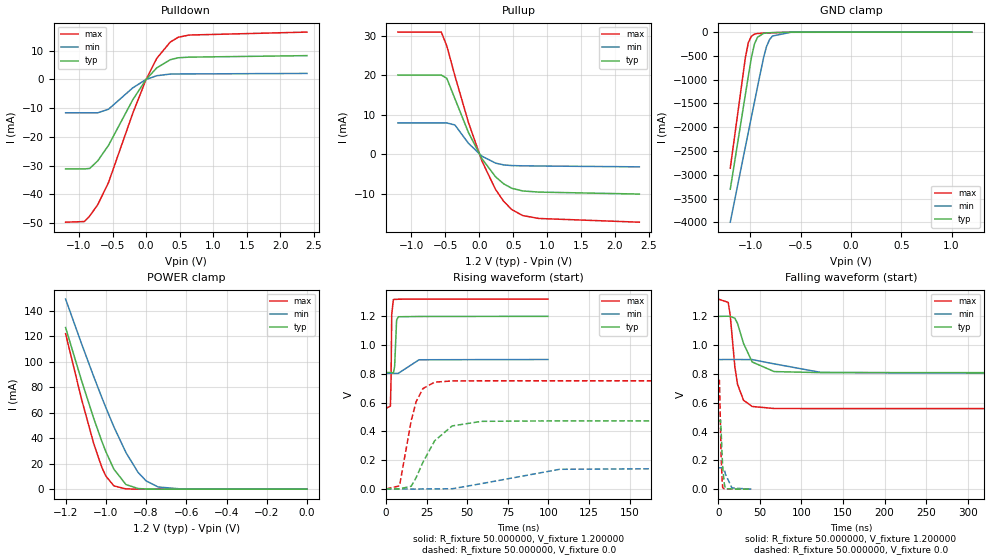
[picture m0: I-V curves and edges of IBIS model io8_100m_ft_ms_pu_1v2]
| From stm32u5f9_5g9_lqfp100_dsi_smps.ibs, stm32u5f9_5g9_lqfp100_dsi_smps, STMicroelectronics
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|   Model io8_100m_ft_ms_pu_1v2
[Model]  io8_100m_ft_ms_pu_1v2
Model_type I/O
Polarity   Non-Inverting
Enable   Active-Low
Vinl =   0.360000V
Vinh =   0.840000V
Vmeas =  0.600000V
Cref =   50.000000pF
Rref =   100.000000M
Vref =   0.0V
C_comp   2.947800pF   2.877700pF   2.996100pF
[Temperature Range]   25.000000   0.140000k   -40.000000
[Pullup Reference]   1.200000V   0.900000V   1.320000V
[Pulldown Reference]   0.0V   0.0V   0.0V
[POWER Clamp Reference]   1.200000V   0.900000V   1.320000V
[GND Clamp Reference]   0.0V   0.0V   0.0V
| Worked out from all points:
|   slope of the pulldown table from 0 to 0.18 V, typ, clamps not added: 40.7 ohm
|   slope of the pullup table from 0 to 0.18 V, typ, clamps not added: 39.5 ohm
|   GND clamp passes 1 mA (typ) near -0.51 V on its own axis
|   POWER clamp passes 1 mA (typ) near -0.86 V on its own axis
|   rising waveform, R_fixture 50.000000, V_fixture 1.200000: 20-80 % time 749ps typ, 2.05ns min, 441ps max; typ from 0.809 V to 1.2 V
|   rising waveform, R_fixture 50.000000, V_fixture 0.0: 20-80 % time 13.8ns typ, 33.6ns min, 7.83ns max; typ from 0.001 V to 0.474 V
|   falling waveform, R_fixture 50.000000, V_fixture 1.200000: 20-80 % time 15.2ns typ, 36.8ns min, 8.74ns max; typ from 1.2 V to 0.809 V
|   falling waveform, R_fixture 50.000000, V_fixture 0.0: 20-80 % time 2.5ns typ, 4.75ns min, 1.85ns max; typ from 0.474 V to 0.001 V
[Pulldown]
|Voltage   I(typ)   I(min)   I(max)
-1.2V     -31.16mA   -11.61mA   -49.71mA
-920mV    -31.16mA   -11.61mA   -49.49mA
-840mV    -31mA      -11.61mA   -47.54mA
-720mV    -28.32mA   -11.61mA   -43.58mA
-560mV    -22.95mA   -10.37mA   -35.89mA
-200mV    -7.146mA   -2.964mA   -11.89mA
0V        0A         0A         0A
160mV     4.047mA    1.298mA    7.361mA
360mV     6.869mA    1.87mA     13mA
480mV     7.543mA    1.91mA     14.69mA
640mV     7.765mA    1.923mA    15.46mA
2.4V      8.291mA    2.091mA    16.49mA
[Pullup]
|Voltage   I(typ)   I(min)   I(max)
-1.2V     20.06mA    7.936mA    30.96mA
-560mV    20.06mA    7.936mA    30.96mA
-480mV    19.26mA    7.936mA    27.49mA
-360mV    14.08mA    7.421mA    19.88mA
-160mV    5.494mA    2.767mA    8.045mA
40mV      -1.16mA    -508.1uA   -1.774mA
240mV     -5.73mA    -2.256mA   -8.953mA
360mV     -7.518mA   -2.715mA   -11.96mA
480mV     -8.639mA   -2.877mA   -14.04mA
640mV     -9.31mA    -2.942mA   -15.55mA
880mV     -9.601mA   -2.986mA   -16.29mA
2.36V     -10.1mA    -3.2mA     -17.23mA
[GND_clamp]
|Voltage   I(typ)   I(min)   I(max)
-1.2V     -3.305A    -3.998A    -2.862A
-1.05V    -1.316A    -2.418A    -539.3mA
-1.02V    -921mA     -2.103A    -218.8mA
-990mV    -539.5mA   -1.788A    -87.43mA
-960mV    -252.1mA   -1.474A    -44.36mA
-930mV    -110.5mA   -1.16A     -30.32mA
-870mV    -28.03mA   -549.1mA   -21.09mA
-840mV    -18.43mA   -305.6mA   -18.27mA
-810mV    -13.9mA    -159.7mA   -15.73mA
-780mV    -11.23mA   -82.35mA   -13.37mA
-600mV    -2.976mA   -4.272mA   -3.058mA
1.2V      0A         14.74nA    0A
[POWER_clamp]
|Voltage   I(typ)   I(min)   I(max)
-1.2V     127mA      149.4mA    122.2mA
-1.12V    84.98mA    114mA      70.29mA
-1.06V    55.52mA    88.42mA    35.69mA
-1.02V    37.64mA    72.04mA    17.19mA
-1V       29.52mA    64.13mA    10.33mA
-960mV    15.7mA     48.99mA    2.596mA
-900mV    3.636mA    28.77mA    207.8uA
-840mV    502.9uA    13.24mA    43.4uA
-800mV    129uA      6.535mA    43.4uA
-740mV    25.52uA    1.726mA    43.4uA
-620mV    25.17uA    82.33uA    35.63uA
0V        0A         17.33nA    0A
[Ramp]
| variable   typ   min   max
dV/dt_r  0.28388/13.82702n   88.99786m/33.60863n 0.45097/7.81542n
dV/dt_f  0.23435/15.13096n   57.82200m/36.77922n 0.45608/8.72717n
R_load = 50.000000
[Rising Waveform]
R_fixture= 50.000000
V_fixture= 1.200000
V_fixture_min= 0.900000
V_fixture_max= 1.320000
|time   V(typ)   V(min)   V(max)
0s        809.5mV    803.6mV    559.9mV
2.803ns   809.5mV    803.6mV    576.1mV
3.203ns   809.5mV    803.6mV    765.1mV
3.604ns   809.4mV    803.6mV    1.212V
4.605ns   805.2mV    803.6mV    1.316V
5.405ns   852.6mV    803.6mV    1.318V
6.607ns   1.173V     803.6mV    1.318V
7.608ns   1.197V     803.6mV    1.319V
20.42ns   1.199V     898.2mV    1.32V
99.7ns    1.2V       900mV      1.32V
[Rising Waveform]
R_fixture= 50.000000
V_fixture= 0.0
V_fixture_min= 0.0
V_fixture_max= 0.0
|time   V(typ)   V(min)   V(max)
0s        593.9uV    601.2uV    547.7uV
8.408ns   791.2uV    600.1uV    21.86mV
15.62ns   19.73mV    -127.6uV   476.6mV
18.62ns   78.89mV    -1.034mV   606.8mV
22.82ns   186.3mV    663.4uV    698.3mV
30.03ns   335.5mV    891.4uV    742.6mV
40.84ns   438.5mV    1.901mV    751.1mV
58.86ns   470.3mV    37.46mV    752mV
106.9ns   473.7mV    137.1mV    752.1mV
299.1ns   473.8mV    149mV      752.2mV
[Falling Waveform]
R_fixture= 50.000000
V_fixture= 1.200000
V_fixture_min= 0.900000
V_fixture_max= 1.320000
|time   V(typ)   V(min)   V(max)
0s        1.2V       900mV      1.32V
12.01ns   1.201V     900.6mV    1.297V
14.41ns   1.2V       900.5mV    1.21V
20.02ns   1.187V     900.5mV    849.2mV
23.22ns   1.151V     900.5mV    728.6mV
30.43ns   1.012V     900.2mV    618mV
40.84ns   883.3mV    899.9mV    574.3mV
67.27ns   816.6mV    870.3mV    560.4mV
123.3ns   809.4mV    811mV      559.8mV
398.8ns   809.5mV    803.6mV    559.9mV
[Falling Waveform]
R_fixture= 50.000000
V_fixture= 0.0
V_fixture_min= 0.0
V_fixture_max= 0.0
|time   V(typ)   V(min)   V(max)
0s        473.8mV    149mV      752.2mV
1.522ns   473.8mV    149mV      756.1mV
2.883ns   479.9mV    149mV      396.3mV
3.604ns   393.9mV    149mV      212.7mV
4.885ns   215.8mV    148.8mV    46.24mV
5.445ns   151.5mV    149.2mV    10.92mV
7.367ns   37.52mV    139mV      3.456mV
8.729ns   4.069mV    104.5mV    2.951mV
16.5ns    1.721mV    8.99mV     1.203mV
39.88ns   593.9uV    601.2uV    547.7uV
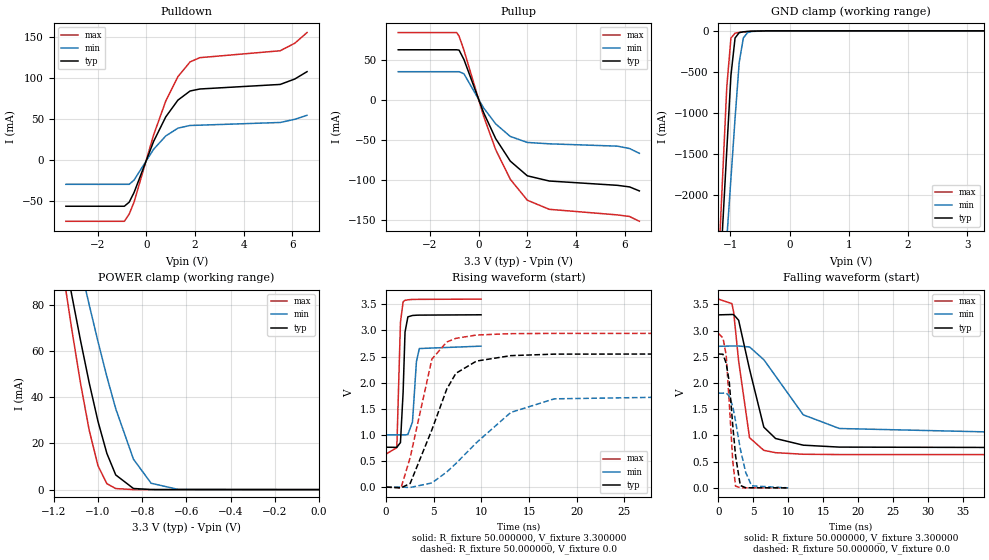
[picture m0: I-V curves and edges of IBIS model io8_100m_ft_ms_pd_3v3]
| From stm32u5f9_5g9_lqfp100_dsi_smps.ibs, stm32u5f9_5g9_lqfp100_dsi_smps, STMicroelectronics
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|   Model io8_100m_ft_ms_pd_3v3
[Model]  io8_100m_ft_ms_pd_3v3
Model_type I/O
Polarity   Non-Inverting
Enable   Active-Low
Vinl =   0.990000V
Vinh =   2.310000V
Vmeas =  1.650000V
Cref =   50.000000pF
Rref =   100.000000M
Vref =   0.0V
C_comp   3.313100pF   3.281800pF   3.354500pF
[Temperature Range]   25.000000   0.140000k   -40.000000
[Pullup Reference]   3.300000V   2.700000V   3.600000V
[Pulldown Reference]   0.0V   0.0V   0.0V
[POWER Clamp Reference]   3.300000V   2.700000V   3.600000V
[GND Clamp Reference]   0.0V   0.0V   0.0V
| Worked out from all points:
|   slope of the pulldown table from 0 to 0.495 V, typ, clamps not added: 14 ohm
|   slope of the pullup table from 0 to 0.495 V, typ, clamps not added: 13.7 ohm
|   GND clamp passes 1 mA (typ) near -0.50 V on its own axis
|   POWER clamp passes 1 mA (typ) near -0.85 V on its own axis
|   rising waveform, R_fixture 50.000000, V_fixture 3.300000: 20-80 % time 250ps typ, 341ps min, 235ps max; typ from 0.764 V to 3.3 V
|   rising waveform, R_fixture 50.000000, V_fixture 0.0: 20-80 % time 3.15ns typ, 6.44ns min, 2.09ns max; typ from 0 V to 2.55 V
|   falling waveform, R_fixture 50.000000, V_fixture 3.300000: 20-80 % time 2.58ns typ, 5.69ns min, 1.62ns max; typ from 3.3 V to 0.764 V
|   falling waveform, R_fixture 50.000000, V_fixture 0.0: 20-80 % time 1ns typ, 1.54ns min, 767ps max; typ from 2.55 V to 0 V
[Pulldown]
|Voltage   I(typ)   I(min)   I(max)
-3.3V     -56.06mA   -29.42mA   -74.35mA
-900mV    -56.06mA   -29.42mA   -74.35mA
-700mV    -51.09mA   -29.42mA   -65.48mA
-500mV    -39.32mA   -24.2mA    -50.88mA
300mV     22.62mA    13.13mA    30.42mA
800mV     52.54mA    29.36mA    71.75mA
1.3V      72.91mA    38.82mA    101.4mA
1.8V      84.02mA    42.13mA    119.4mA
2.2V      86.43mA    42.46mA    124.5mA
5.5V      91.98mA    45.75mA    132.9mA
6.1V      98.6mA     49.6mA     142.1mA
6.6V      107.5mA    54.5mA     155mA
[Pullup]
|Voltage   I(typ)   I(min)   I(max)
-3.3V     62.56mA    35.12mA    84.08mA
-900mV    62.56mA    35.12mA    84.08mA
-800mV    62.09mA    35.12mA    79.52mA
-600mV    50.26mA    32.46mA    61.94mA
200mV     -15.65mA   -9.933mA   -19.95mA
700mV     -48.51mA   -30.11mA   -62.22mA
1.3V      -76.68mA   -45.83mA   -99.4mA
2V        -95.1mA    -53.38mA   -125.6mA
2.9V      -101.6mA   -55.08mA   -137mA
5.7V      -107mA     -58mA      -144mA
6.2V      -109mA     -61mA      -146mA
6.6V      -114mA     -67mA      -152mA
[GND_clamp]
|Voltage   I(typ)   I(min)   I(max)
-3.3V     -9.848A    -9.957A    -9.458A
-1.2V     -3.312A    -4.013A    -2.863A
-1.13V    -2.381A    -3.274A    -1.769A
-1.06V    -1.452A    -2.535A    -684.8mA
-990mV    -542.9mA   -1.798A    -88.04mA
-920mV    -87.13mA   -1.064A    -28.45mA
-850mV    -22.11mA   -382.4mA   -19.62mA
-780mV    -11.98mA   -86.98mA   -13.73mA
-710mV    -7.63mA    -22.27mA   -8.759mA
-640mV    -4.504mA   -7.781mA   -4.831mA
-360mV    -39.8uA    -178.9uA   -19.56uA
3.28V     83.52uA    56.87uA    102.4uA
[POWER_clamp]
|Voltage   I(typ)   I(min)   I(max)
-3.28V    1.355A     1.167A     1.664A
-1.16V    105.7mA    131.6mA    95.69mA
-1.12V    84.97mA    114mA      70.27mA
-1.08V    65.05mA    96.83mA    46.54mA
-1.04V    46.34mA    80.15mA    25.76mA
-1V       29.51mA    64.13mA    10.3mA
-960mV    15.69mA    48.99mA    2.571mA
-920mV    6.373mA    35.1mA     455.6uA
-840mV    490.7uA    13.24mA    11.36uA
-760mV    27.33uA    2.767mA    276.6nA
-640mV    346.6nA    134.1uA    15.62nA
0V        0A         19.91nA    0A
[Ramp]
| variable   typ   min   max
dV/dt_r  1.53198/3.14524n   1.08384/6.43668n   1.76610/2.08484n
dV/dt_f  1.52117/2.57475n   1.01862/5.67621n   1.77920/1.61705n
R_load = 50.000000
[Rising Waveform]
R_fixture= 50.000000
V_fixture= 3.300000
V_fixture_min= 2.700000
V_fixture_max= 3.600000
|time   V(typ)   V(min)   V(max)
0s        763.9mV    1.001V     633.7mV
1.121ns   761mV      1.001V     757.1mV
1.502ns   853.1mV    1.001V     3.154V
1.782ns   1.818V     1.001V     3.549V
1.982ns   2.968V     998.9mV    3.576V
2.282ns   3.259V     1.008V     3.586V
2.763ns   3.286V     1.245V     3.593V
3.183ns   3.291V     2.407V     3.594V
3.483ns   3.293V     2.653V     3.595V
9.97ns    3.299V     2.699V     3.599V
[Rising Waveform]
R_fixture= 50.000000
V_fixture= 0.0
V_fixture_min= 0.0
V_fixture_max= 0.0
|time   V(typ)   V(min)   V(max)
0s        9.551uV    6.88uV     8.861uV
1.562ns   -13.37mV   62.21uV    -14.3mV
2.523ns   70.26mV    -6.954mV   566.1mV
4.805ns   1.098V     80.22mV    2.451V
6.366ns   1.877V     289.8mV    2.778V
7.327ns   2.179V     452mV      2.848V
9.489ns   2.413V     851.3mV    2.912V
13.09ns   2.517V     1.43V      2.938V
17.66ns   2.546V     1.69V      2.943V
59.82ns   2.553V     1.806V     2.943V
[Falling Waveform]
R_fixture= 50.000000
V_fixture= 3.300000
V_fixture_min= 2.700000
V_fixture_max= 3.600000
|time   V(typ)   V(min)   V(max)
0s        3.299V     2.699V     3.599V
1.922ns   3.306V     2.705V     3.514V
2.162ns   3.305V     2.705V     3.36V
2.883ns   3.196V     2.705V     2.419V
4.444ns   2.262V     2.687V     955.9mV
6.486ns   1.158V     2.444V     715.7mV
8.168ns   941.2mV    2.132V     671mV
12.13ns   814mV      1.393V     640.8mV
17.3ns    777.2mV    1.132V     635.1mV
59.82ns   763.9mV    1.001V     633.7mV
[Falling Waveform]
R_fixture= 50.000000
V_fixture= 0.0
V_fixture_min= 0.0
V_fixture_max= 0.0
|time   V(typ)   V(min)   V(max)
0s        2.553V     1.806V     2.943V
640.6ps   2.548V     1.806V     2.859V
1.101ns   2.375V     1.809V     2.534V
1.542ns   2.021V     1.75V      1.626V
2.042ns   1.191V     1.553V     509.6mV
2.442ns   612.9mV    1.271V     33.98mV
3.123ns   45.26mV    741mV      2.027mV
3.904ns   2.538mV    291mV      980.9uV
4.745ns   1.095mV    38.37mV    632.5uV
9.97ns    9.551uV    6.88uV     8.861uV
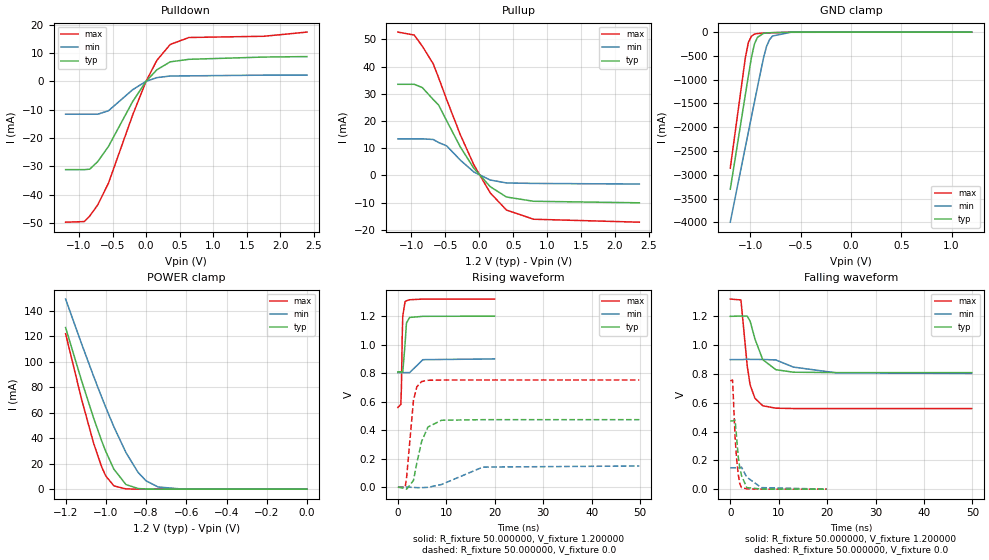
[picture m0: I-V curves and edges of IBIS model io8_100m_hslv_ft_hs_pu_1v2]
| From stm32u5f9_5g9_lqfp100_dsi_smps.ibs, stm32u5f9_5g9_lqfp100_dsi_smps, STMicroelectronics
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|   Model io8_100m_hslv_ft_hs_pu_1v2
[Model]  io8_100m_hslv_ft_hs_pu_1v2
Model_type I/O
Polarity   Non-Inverting
Enable   Active-Low
Vinl =   0.360000V
Vinh =   0.840000V
Vmeas =  0.600000V
Cref =   50.000000pF
Rref =   100.000000M
Vref =   0.0V
C_comp   3.030100pF   2.960800pF   3.078300pF
[Temperature Range]   25.000000   0.140000k   -40.000000
[Pullup Reference]   1.200000V   0.900000V   1.320000V
[Pulldown Reference]   0.0V   0.0V   0.0V
[POWER Clamp Reference]   1.200000V   0.900000V   1.320000V
[GND Clamp Reference]   0.0V   0.0V   0.0V
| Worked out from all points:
|   slope of the pulldown table from 0 to 0.18 V, typ, clamps not added: 40.7 ohm
|   slope of the pullup table from 0 to 0.18 V, typ, clamps not added: 39.5 ohm
|   GND clamp passes 1 mA (typ) near -0.51 V on its own axis
|   POWER clamp passes 1 mA (typ) near -0.86 V on its own axis
|   rising waveform, R_fixture 50.000000, V_fixture 1.200000: 20-80 % time 361ps typ, 838ps min, 237ps max; typ from 0.81 V to 1.2 V
|   rising waveform, R_fixture 50.000000, V_fixture 0.0: 20-80 % time 2ns typ, 4.56ns min, 1.18ns max; typ from 0.001 V to 0.474 V
|   falling waveform, R_fixture 50.000000, V_fixture 1.200000: 20-80 % time 2.45ns typ, 5.46ns min, 1.5ns max; typ from 1.2 V to 0.81 V
|   falling waveform, R_fixture 50.000000, V_fixture 0.0: 20-80 % time 1.06ns typ, 2ns min, 809ps max; typ from 0.474 V to 0.001 V
[Pulldown]
|Voltage   I(typ)   I(min)   I(max)
-1.2V     -31.16mA   -11.61mA   -49.71mA
-920mV    -31.16mA   -11.61mA   -49.49mA
-840mV    -31mA      -11.61mA   -47.54mA
-720mV    -28.32mA   -11.61mA   -43.58mA
-560mV    -22.95mA   -10.37mA   -35.89mA
-200mV    -7.146mA   -2.964mA   -11.89mA
0V        0A         0A         0A
160mV     4.047mA    1.298mA    7.361mA
360mV     6.869mA    1.87mA     13mA
640mV     7.765mA    1.923mA    15.46mA
1.76V     8.563mA    2.178mA    15.9mA
2.4V      8.725mA    2.178mA    17.37mA
[Pullup]
|Voltage   I(typ)   I(min)   I(max)
-1.2V     33.49mA    13.42mA    52.69mA
-960mV    33.49mA    13.42mA    51.6mA
-840mV    32.28mA    13.42mA    47.5mA
-680mV    27.89mA    13.19mA    41.04mA
-600mV    25.86mA    12.07mA    35.87mA
-480mV    20.01mA    10.82mA    27.79mA
-280mV    10.44mA    5.592mA    14.93mA
-80mV     2.58mA     1.232mA    3.849mA
160mV     -4.145mA   -1.713mA   -6.415mA
400mV     -7.963mA   -2.792mA   -12.75mA
800mV     -9.537mA   -2.973mA   -16.14mA
2.36V     -10.1mA    -3.2mA     -17.23mA
[GND_clamp]
|Voltage   I(typ)   I(min)   I(max)
-1.2V     -3.305A    -3.998A    -2.862A
-1.05V    -1.316A    -2.418A    -539.3mA
-1.02V    -921mA     -2.103A    -218.8mA
-990mV    -539.5mA   -1.788A    -87.43mA
-960mV    -252.1mA   -1.474A    -44.36mA
-930mV    -110.5mA   -1.16A     -30.32mA
-870mV    -28.03mA   -549.1mA   -21.09mA
-840mV    -18.43mA   -305.6mA   -18.27mA
-810mV    -13.9mA    -159.7mA   -15.73mA
-780mV    -11.23mA   -82.35mA   -13.37mA
-600mV    -2.976mA   -4.272mA   -3.058mA
1.2V      0A         14.73nA    0A
[POWER_clamp]
|Voltage   I(typ)   I(min)   I(max)
-1.2V     127mA      149.4mA    122.2mA
-1.12V    84.98mA    114mA      70.29mA
-1.06V    55.52mA    88.42mA    35.69mA
-1.02V    37.64mA    72.04mA    17.19mA
-1V       29.52mA    64.13mA    10.33mA
-960mV    15.7mA     48.99mA    2.596mA
-900mV    3.636mA    28.77mA    207.8uA
-840mV    502.9uA    13.24mA    43.56uA
-800mV    129uA      6.535mA    43.56uA
-740mV    25.39uA    1.726mA    43.56uA
-620mV    25.22uA    82.33uA    36.06uA
0V        0A         17.33nA    0A
[Ramp]
| variable   typ   min   max
dV/dt_r  0.28389/1.99855n   89.00985m/4.55790n  0.45096/1.18295n
dV/dt_f  0.23433/2.45012n   57.81000m/5.44909n  0.45608/1.50253n
R_load = 50.000000
[Rising Waveform]
R_fixture= 50.000000
V_fixture= 1.200000
V_fixture_min= 0.900000
V_fixture_max= 1.320000
|time   V(typ)   V(min)   V(max)
0s        809.5mV    803.6mV    560mV
600.6ps   810.2mV    803.7mV    581mV
720.7ps   810.1mV    803.7mV    700.8mV
880.9ps   808.6mV    803.7mV    1.048V
1.001ns   807.3mV    803.7mV    1.202V
1.481ns   1.01V      803.7mV    1.302V
1.762ns   1.152V     803.8mV    1.308V
2.402ns   1.191V     803.8mV    1.315V
5.165ns   1.199V     894.8mV    1.32V
19.94ns   1.2V       900mV      1.32V
[Rising Waveform]
R_fixture= 50.000000
V_fixture= 0.0
V_fixture_min= 0.0
V_fixture_max= 0.0
|time   V(typ)   V(min)   V(max)
0s        577.1uV    593.9uV    496.9uV
1.502ns   -9.364mV   559.9uV    948.3uV
1.802ns   -13.72mV   562.4uV    71.35mV
3.203ns   47.25mV    -1.305mV   608.1mV
3.904ns   170mV      -3.121mV   704.6mV
4.905ns   322.2mV    -3.385mV   741.4mV
6.206ns   422.6mV    -640.8uV   750.2mV
9.009ns   469.8mV    19.3mV     752.1mV
17.52ns   473.8mV    141.2mV    752.3mV
49.85ns   473.8mV    149mV      752.3mV
[Falling Waveform]
R_fixture= 50.000000
V_fixture= 1.200000
V_fixture_min= 0.900000
V_fixture_max= 1.320000
|time   V(typ)   V(min)   V(max)
0s        1.2V       900mV      1.32V
2.202ns   1.202V     899.6mV    1.314V
3.504ns   1.202V     902mV      856mV
4.104ns   1.166V     901.5mV    723.8mV
5.105ns   1.042V     900.9mV    630.9mV
6.707ns   899.6mV    900.7mV    579.4mV
9.409ns   829.9mV    897.5mV    562.6mV
13.01ns   812.3mV    848mV      560.2mV
21.82ns   809.5mV    808.1mV    560mV
49.85ns   809.5mV    803.6mV    560mV
[Falling Waveform]
R_fixture= 50.000000
V_fixture= 0.0
V_fixture_min= 0.0
V_fixture_max= 0.0
|time   V(typ)   V(min)   V(max)
0s        473.8mV    149mV      752.3mV
480.5ps   474mV      149.1mV    758mV
1.001ns   480.2mV    149.1mV    358.7mV
1.281ns   370.6mV    149.1mV    220.5mV
1.642ns   226.1mV    149mV      105.7mV
1.962ns   150.1mV    149.5mV    38.71mV
2.322ns   95.05mV    153.3mV    11.44mV
3.403ns   11.24mV    84.02mV    2.329mV
6.406ns   1.373mV    11.16mV    630.2uV
19.94ns   577.1uV    593.9uV    496.9uV
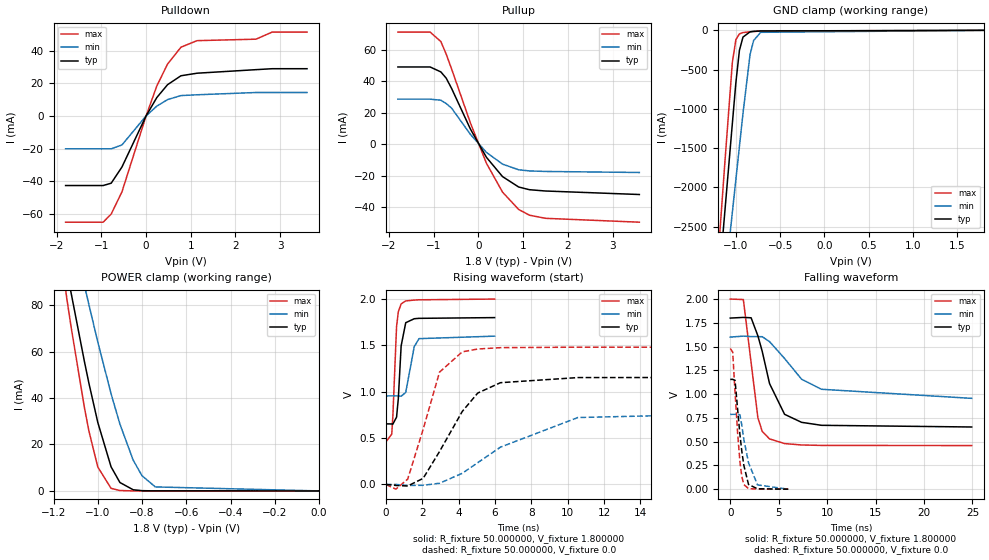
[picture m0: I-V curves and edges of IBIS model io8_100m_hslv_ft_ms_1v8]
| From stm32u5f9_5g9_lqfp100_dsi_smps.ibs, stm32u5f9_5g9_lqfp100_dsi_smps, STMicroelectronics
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|   Model io8_100m_hslv_ft_ms_1v8
[Model]  io8_100m_hslv_ft_ms_1v8
Model_type I/O
Polarity   Non-Inverting
Enable   Active-Low
Vinl =   0.540000V
Vinh =   1.260000V
Vmeas =  0.900000V
Cref =   50.000000pF
Rref =   100.000000M
Vref =   0.0V
C_comp   3.235100pF   3.233200pF   3.282800pF
[Temperature Range]   25.000000   0.140000k   -40.000000
[Pullup Reference]   1.800000V   1.600000V   2.000000V
[Pulldown Reference]   0.0V   0.0V   0.0V
[POWER Clamp Reference]   1.800000V   1.600000V   2.000000V
[GND Clamp Reference]   0.0V   0.0V   0.0V
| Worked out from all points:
|   slope of the pulldown table from 0 to 0.27 V, typ, clamps not added: 21.7 ohm
|   slope of the pullup table from 0 to 0.27 V, typ, clamps not added: 22.6 ohm
|   GND clamp passes 1 mA (typ) near -0.51 V on its own axis
|   POWER clamp passes 1 mA (typ) near -0.86 V on its own axis
|   rising waveform, R_fixture 50.000000, V_fixture 1.800000: 20-80 % time 207ps typ, 322ps min, 193ps max; typ from 0.654 V to 1.8 V
|   rising waveform, R_fixture 50.000000, V_fixture 0.0: 20-80 % time 2.12ns typ, 4.11ns min, 1.26ns max; typ from 0 V to 1.16 V
|   falling waveform, R_fixture 50.000000, V_fixture 1.800000: 20-80 % time 1.9ns typ, 3.69ns min, 1.06ns max; typ from 1.8 V to 0.654 V
|   falling waveform, R_fixture 50.000000, V_fixture 0.0: 20-80 % time 742ps typ, 1.01ns min, 588ps max; typ from 1.16 V to 0 V
[Pulldown]
|Voltage   I(typ)   I(min)   I(max)
-1.8V     -42.74mA   -20.21mA   -65.25mA
-960mV    -42.74mA   -20.21mA   -65.25mA
-780mV    -41.3mA    -20.21mA   -60.25mA
-540mV    -31.39mA   -17.82mA   -46.65mA
0V        -10fA      -600fA     0A
240mV     11.28mA    6.002mA    18.38mA
480mV     19.18mA    10.02mA    31.83mA
780mV     24.67mA    12.5mA     42.21mA
1.14V     26.24mA    12.99mA    46.23mA
2.46V     28.42mA    14.39mA    47.14mA
2.82V     29mA       14.39mA    51.49mA
3.6V      29mA       14.39mA    51.49mA
[Pullup]
|Voltage   I(typ)   I(min)   I(max)
-1.8V     49.09mA    28.63mA    71.27mA
-1.08V    49.09mA    28.63mA    71.27mA
-840mV    45.95mA    27.95mA    65.26mA
-720mV    41.97mA    25.84mA    57.25mA
-600mV    35.46mA    22.93mA    47.86mA
-180mV    9.685mA    6.268mA    13.58mA
180mV     -8.368mA   -5.234mA   -12.14mA
540mV     -20.62mA   -12.68mA   -30.5mA
900mV     -27.22mA   -16.28mA   -41.49mA
1.14V     -28.94mA   -17mA      -45.14mA
1.5V      -29.77mA   -17.34mA   -47.14mA
3.6V      -32mA      -18mA      -49.6mA
[GND_clamp]
|Voltage   I(typ)   I(min)   I(max)
-1.8V     -9.707A    -9.942A    -9.774A
-1.2V     -3.309A    -4.006A    -2.864A
-1.16V    -2.777A    -3.584A    -2.239A
-1.12V    -2.246A    -3.162A    -1.614A
-1.04V    -1.186A    -2.319A    -408.6mA
-1V       -663.9mA   -1.898A    -117.8mA
-960mV    -254mA     -1.478A    -45.14mA
-920mV    -86.03mA   -1.06A     -28.58mA
-840mV    -19.12mA   -308.9mA   -18.74mA
-800mV    -13.39mA   -130.8mA   -15.31mA
-720mV    -7.948mA   -25.37mA   -9.381mA
1.8V      0A         14.95nA    0A
[POWER_clamp]
|Voltage   I(typ)   I(min)   I(max)
-1.8V     470.8mA    433.7mA    554.6mA
-1.14V    95.25mA    122.7mA    82.82mA
-1.12V    84.97mA    114mA      70.27mA
-1.06V    55.51mA    88.42mA    35.67mA
-1.04V    46.34mA    80.15mA    25.76mA
-1V       29.51mA    64.13mA    10.3mA
-940mV    10.39mA    41.86mA    1.109mA
-900mV    3.624mA    28.77mA    182.8uA
-840mV    490.7uA    13.24mA    11.35uA
-800mV    116.8uA    6.532mA    1.77uA
-740mV    13.2uA     1.723mA    109.2nA
0V        0A         18.72nA    0A
[Ramp]
| variable   typ   min   max
dV/dt_r  0.69300/2.11678n   0.47191/4.10933n   0.88872/1.25667n
dV/dt_f  0.68761/1.89693n   0.38621/3.68761n   0.92481/1.05271n
R_load = 50.000000
[Rising Waveform]
R_fixture= 50.000000
V_fixture= 1.800000
V_fixture_min= 1.600000
V_fixture_max= 2.000000
|time   V(typ)   V(min)   V(max)
0s        654mV      955.4mV    458.7mV
324.3ps   652.7mV    955.5mV    542.8mV
384.4ps   650.8mV    955.6mV    733.7mV
588.6ps   726.3mV    955.7mV    1.703V
684.7ps   924mV      955.3mV    1.863V
840.8ps   1.495V     952.1mV    1.948V
1.093ns   1.745V     992.8mV    1.98V
1.562ns   1.788V     1.487V     1.989V
1.826ns   1.792V     1.573V     1.992V
5.982ns   1.8V       1.6V       2V
[Rising Waveform]
R_fixture= 50.000000
V_fixture= 0.0
V_fixture_min= 0.0
V_fixture_max= 0.0
|time   V(typ)   V(min)   V(max)
0s        -90.99uV   -18.92uV   -77.38uV
550.6ps   -10.41mV   -58.53uV   -50.74mV
1.201ns   -16.56mV   -11.09mV   57.52mV
2.052ns   65.94mV    -9mV       595.3mV
2.953ns   355.7mV    13.27mV    1.212V
4.204ns   788mV      120.5mV    1.431V
5.055ns   986.2mV    235.1mV    1.461V
6.306ns   1.098V     402.7mV    1.476V
10.56ns   1.153V     721.9mV    1.481V
24.92ns   1.155V     786.9mV    1.481V
[Falling Waveform]
R_fixture= 50.000000
V_fixture= 1.800000
V_fixture_min= 1.600000
V_fixture_max= 2.000000
|time   V(typ)   V(min)   V(max)
0s        1.8V       1.6V       2V
1.351ns   1.807V     1.61V      1.995V
2.152ns   1.803V     1.605V     1.331V
2.853ns   1.613V     1.605V     750mV
3.303ns   1.448V     1.604V     607.4mV
4.054ns   1.111V     1.552V     528.8mV
5.606ns   787.5mV    1.375V     479.5mV
7.357ns   703.2mV    1.157V     464.9mV
9.409ns   671.8mV    1.051V     460.3mV
24.92ns   654mV      955.4mV    458.7mV
[Falling Waveform]
R_fixture= 50.000000
V_fixture= 0.0
V_fixture_min= 0.0
V_fixture_max= 0.0
|time   V(typ)   V(min)   V(max)
0s        1.155V     786.9mV    1.481V
252.3ps   1.155V     787mV      1.441V
492.5ps   1.145V     787.1mV    1.019V
768.8ps   830.5mV    790.1mV    577.6mV
997ps     575.2mV    781.3mV    289.4mV
1.189ns   401.1mV    674.1mV    133mV
1.405ns   248.3mV    521.3mV    48.76mV
1.886ns   49.22mV    277.2mV    5.119mV
2.811ns   3.784mV    44.74mV    1.426mV
5.982ns   -90.99uV   -18.92uV   -77.38uV
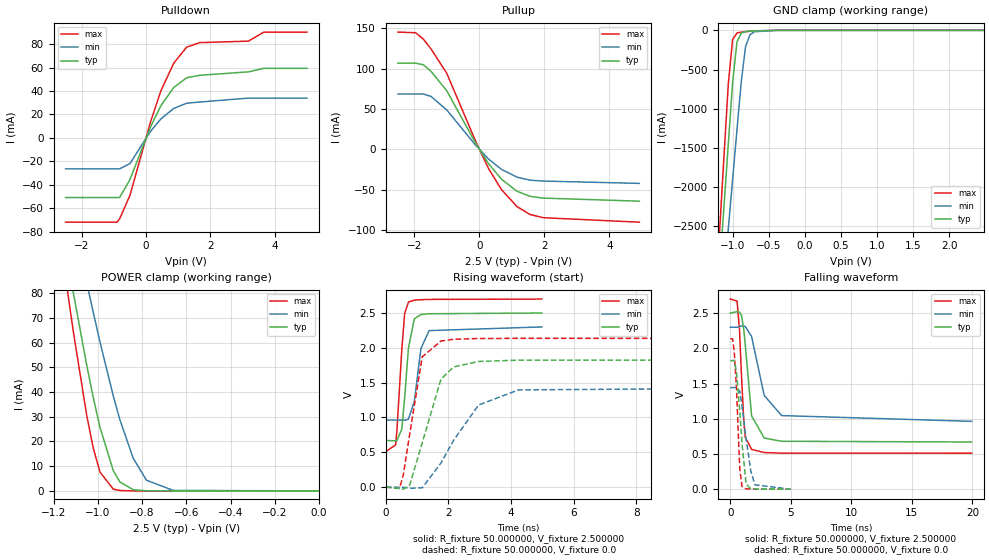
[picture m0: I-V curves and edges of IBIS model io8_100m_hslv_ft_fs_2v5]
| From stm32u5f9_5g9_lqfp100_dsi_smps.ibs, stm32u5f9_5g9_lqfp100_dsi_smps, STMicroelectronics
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|   Model io8_100m_hslv_ft_fs_2v5
[Model]  io8_100m_hslv_ft_fs_2v5
Model_type I/O
Polarity   Non-Inverting
Enable   Active-Low
Vinl =   0.750000V
Vinh =   1.750000V
Vmeas =  1.250000V
Cref =   50.000000pF
Rref =   100.000000M
Vref =   0.0V
C_comp   3.340900pF   3.338500pF   3.380300pF
[Temperature Range]   25.000000   0.140000k   -40.000000
[Pullup Reference]   2.500000V   2.300000V   2.700000V
[Pulldown Reference]   0.0V   0.0V   0.0V
[POWER Clamp Reference]   2.500000V   2.300000V   2.700000V
[GND Clamp Reference]   0.0V   0.0V   0.0V
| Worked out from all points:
|   slope of the pulldown table from 0 to 0.375 V, typ, clamps not added: 16.1 ohm
|   slope of the pullup table from 0 to 0.375 V, typ, clamps not added: 16.6 ohm
|   GND clamp passes 1 mA (typ) near -0.50 V on its own axis
|   POWER clamp passes 1 mA (typ) near -0.86 V on its own axis
|   rising waveform, R_fixture 50.000000, V_fixture 2.500000: 20-80 % time 200ps typ, 231ps min, 180ps max; typ from 0.67 V to 2.5 V
|   rising waveform, R_fixture 50.000000, V_fixture 0.0: 20-80 % time 661ps typ, 1.22ns min, 424ps max; typ from 0 V to 1.82 V
|   falling waveform, R_fixture 50.000000, V_fixture 2.500000: 20-80 % time 569ps typ, 1.09ns min, 362ps max; typ from 2.5 V to 0.67 V
|   falling waveform, R_fixture 50.000000, V_fixture 0.0: 20-80 % time 467ps typ, 672ps min, 321ps max; typ from 1.82 V to 0 V
[Pulldown]
|Voltage   I(typ)   I(min)   I(max)
-2.5V     -51mA      -26.45mA   -72.04mA
-900mV    -51mA      -26.45mA   -72.04mA
-820mV    -50.89mA   -26.45mA   -69.09mA
-500mV    -35.59mA   -21.93mA   -49.09mA
140mV     9.489mA    5.639mA    13.76mA
460mV     27.5mA     16.24mA    40.22mA
860mV     43.07mA    25.18mA    63.88mA
1.26V     51.38mA    29.65mA    77.49mA
1.66V     53.45mA    30.63mA    81.42mA
3.18V     56.44mA    34.01mA    82.68mA
3.66V     59.44mA    34.01mA    90.42mA
5V        59.44mA    34.01mA    90.42mA
[Pullup]
|Voltage   I(typ)   I(min)   I(max)
-2.5V     106.8mA    68.58mA    145.2mA
-1.96V    106.8mA    68.58mA    144.4mA
-1.72V    104.8mA    68.58mA    136.6mA
-1.48V    96.52mA    65.55mA    124.2mA
-1V       72.68mA    48.88mA    94.23mA
-120mV    8.307mA    5.657mA    10.97mA
280mV     -17.4mA    -11.68mA   -23.32mA
680mV     -36.72mA   -24.56mA   -49.54mA
1.16V     -51.75mA   -34.32mA   -70.71mA
1.56V     -58mA      -38.01mA   -80.45mA
1.96V     -60.18mA   -39.11mA   -84.44mA
4.92V     -64mA      -42mA      -90mA
[GND_clamp]
|Voltage   I(typ)   I(min)   I(max)
-2.5V     -9.446A    -9.524A    -9.146A
-1.18V    -3.045A    -3.8A      -2.552A
-1.12V    -2.248A    -3.166A    -1.614A
-1.06V    -1.452A    -2.533A    -685.3mA
-1V       -665mA     -1.901A    -117.9mA
-940mV    -148mA     -1.272A    -34.32mA
-880mV    -35.13mA   -651.5mA   -22.79mA
-820mV    -16mA      -203.9mA   -17.07mA
-760mV    -10.46mA   -56.88mA   -12.26mA
-700mV    -7.068mA   -18.52mA   -8.146mA
-400mV    -103.3uA   -375.9uA   -42.12uA
2.48V     0A         14.84nA    0A
[POWER_clamp]
|Voltage   I(typ)   I(min)   I(max)
-2.49V    881mA      773.1mA    1.07A
-1.14V    95.25mA    122.7mA    82.82mA
-1.11V    79.9mA     109.7mA    64.14mA
-1.05V    50.87mA    84.26mA    30.57mA
-1.02V    37.63mA    72.04mA    17.17mA
-990mV    25.71mA    60.25mA    7.621mA
-930mV    8.217mA    38.43mA    713.9uA
-900mV    3.624mA    28.77mA    182.8uA
-840mV    490.7uA    13.24mA    11.35uA
-780mV    56.55uA    4.324mA    699nA
-660mV    716.5nA    226uA      9.775nA
0V        0A         19.49nA    0A
[Ramp]
| variable   typ   min   max
dV/dt_r  1.09512/0.65950n   0.86592/1.21872n   1.28196/0.42339n
dV/dt_f  1.09811/0.56828n   0.80213/1.08931n   1.31360/0.36160n
R_load = 50.000000
[Rising Waveform]
R_fixture= 50.000000
V_fixture= 2.500000
V_fixture_min= 2.300000
V_fixture_max= 2.700000
|time   V(typ)   V(min)   V(max)
0s        669.8mV    963.1mV    510.6mV
310.3ps   664.3mV    963.5mV    606.4mV
350.4ps   665mV      963.5mV    793.7mV
510.5ps   834.1mV    962.4mV    1.978V
600.6ps   1.283V     959.9mV    2.49V
720.7ps   1.993V     976.4mV    2.656V
910.9ps   2.417V     1.23V      2.685V
1.121ns   2.478V     1.989V     2.691V
1.381ns   2.489V     2.247V     2.695V
4.985ns   2.5V       2.3V       2.7V
[Rising Waveform]
R_fixture= 50.000000
V_fixture= 0.0
V_fixture_min= 0.0
V_fixture_max= 0.0
|time   V(typ)   V(min)   V(max)
0s        -172.3uV   -49.94uV   -144.5uV
440.4ps   -21.98mV   -195.2uV   -12.06mV
560.6ps   -29.37mV   -1.622mV   181.7mV
760.8ps   28.65mV    -16.98mV   756.8mV
1.161ns   634.5mV    -10.07mV   1.87V
1.762ns   1.551V     346.1mV    2.098V
2.162ns   1.725V     670mV      2.122V
2.963ns   1.804V     1.179V     2.134V
4.244ns   1.823V     1.396V     2.136V
19.94ns   1.825V     1.443V     2.136V
[Falling Waveform]
R_fixture= 50.000000
V_fixture= 2.500000
V_fixture_min= 2.300000
V_fixture_max= 2.700000
|time   V(typ)   V(min)   V(max)
0s        2.5V       2.3V       2.7V
560.6ps   2.522V     2.299V     2.672V
760.8ps   2.514V     2.314V     2.271V
920.9ps   2.471V     2.318V     1.635V
1.121ns   2.259V     2.314V     959.2mV
1.241ns   2.048V     2.311V     737.3mV
1.762ns   1.041V     2.168V     564.7mV
2.803ns   726.5mV    1.331V     519.9mV
4.244ns   680mV      1.045V     511.8mV
19.94ns   669.8mV    963.1mV    510.6mV
[Falling Waveform]
R_fixture= 50.000000
V_fixture= 0.0
V_fixture_min= 0.0
V_fixture_max= 0.0
|time   V(typ)   V(min)   V(max)
0s        1.825V     1.443V     2.136V
190.2ps   1.825V     1.443V     2.137V
330.3ps   1.832V     1.443V     1.954V
510.5ps   1.666V     1.444V     1.443V
780.8ps   1.124V     1.394V     300.1mV
971ps     644.2mV    1.183V     36.47mV
1.311ns   72.95mV    712.5mV    4.3mV
1.702ns   5.674mV    251.4mV    2.32mV
2.042ns   3.155mV    60.83mV    1.392mV
4.985ns   -172.3uV   -49.94uV   -144.5uV
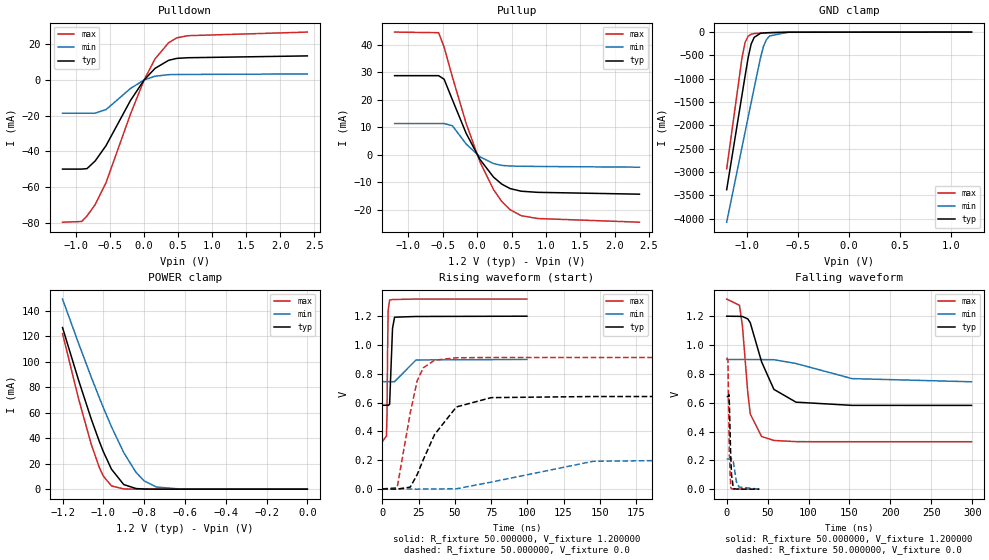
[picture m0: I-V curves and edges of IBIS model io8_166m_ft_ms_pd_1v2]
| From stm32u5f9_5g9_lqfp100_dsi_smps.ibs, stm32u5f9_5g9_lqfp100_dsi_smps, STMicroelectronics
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|   Model io8_166m_ft_ms_pd_1v2
[Model]  io8_166m_ft_ms_pd_1v2
Model_type I/O
Polarity   Non-Inverting
Enable   Active-Low
Vinl =   0.360000V
Vinh =   0.840000V
Vmeas =  0.600000V
Cref =   50.000000pF
Rref =   100.000000M
Vref =   0.0V
C_comp   3.151500pF   3.086800pF   3.197700pF
[Temperature Range]   25.000000   0.140000k   -40.000000
[Pullup Reference]   1.200000V   0.900000V   1.320000V
[Pulldown Reference]   0.0V   0.0V   0.0V
[POWER Clamp Reference]   1.200000V   0.900000V   1.320000V
[GND Clamp Reference]   0.0V   0.0V   0.0V
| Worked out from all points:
|   slope of the pulldown table from 0 to 0.18 V, typ, clamps not added: 25.4 ohm
|   slope of the pullup table from 0 to 0.18 V, typ, clamps not added: 27.8 ohm
|   GND clamp passes 1 mA (typ) near -0.51 V on its own axis
|   POWER clamp passes 1 mA (typ) near -0.86 V on its own axis
|   rising waveform, R_fixture 50.000000, V_fixture 1.200000: 20-80 % time 1.13ns typ, 3.04ns min, 565ps max; typ from 0.581 V to 1.2 V
|   rising waveform, R_fixture 50.000000, V_fixture 0.0: 20-80 % time 19.5ns typ, 48.3ns min, 9.61ns max; typ from 0 V to 0.642 V
|   falling waveform, R_fixture 50.000000, V_fixture 1.200000: 20-80 % time 22ns typ, 55.2ns min, 9.26ns max; typ from 1.2 V to 0.581 V
|   falling waveform, R_fixture 50.000000, V_fixture 0.0: 20-80 % time 1.97ns typ, 3.66ns min, 1.47ns max; typ from 0.642 V to 0 V
[Pulldown]
|Voltage   I(typ)   I(min)   I(max)
-1.2V     -49.86mA   -18.57mA   -79.56mA
-920mV    -49.86mA   -18.57mA   -79.19mA
-840mV    -49.6mA    -18.57mA   -76.08mA
-720mV    -45.32mA   -18.57mA   -69.74mA
-560mV    -36.71mA   -16.58mA   -57.44mA
-200mV    -11.43mA   -4.74mA    -19.03mA
0V        -10fA      -500fA     0A
160mV     6.477mA    2.075mA    11.78mA
360mV     10.99mA    2.99mA     20.81mA
480mV     12.07mA    3.054mA    23.53mA
640mV     12.43mA    3.075mA    24.76mA
2.4V      13.46mA    3.369mA    26.78mA
[Pullup]
|Voltage   I(typ)   I(min)   I(max)
-1.2V     28.73mA    11.35mA    44.55mA
-560mV    28.73mA    11.35mA    44.33mA
-480mV    27.44mA    11.35mA    39.12mA
-360mV    20.01mA    10.56mA    28.26mA
-160mV    7.809mA    3.931mA    11.44mA
40mV      -1.648mA   -721.3uA   -2.521mA
240mV     -8.14mA    -3.2mA     -12.72mA
360mV     -10.68mA   -3.85mA    -16.99mA
480mV     -12.27mA   -4.078mA   -19.94mA
640mV     -13.22mA   -4.169mA   -22.09mA
880mV     -13.63mA   -4.232mA   -23.14mA
2.36V     -14.3mA    -4.5mA     -24.47mA
[GND_clamp]
|Voltage   I(typ)   I(min)   I(max)
-1.2V     -3.379A    -4.076A    -2.932A
-1.05V    -1.35A     -2.47A     -550.7mA
-1.02V    -947.8mA   -2.15A     -221.5mA
-990mV    -552.4mA   -1.829A    -88.45mA
-960mV    -255.3mA   -1.51A     -44.89mA
-930mV    -111.8mA   -1.191A    -30.7mA
-870mV    -28.37mA   -564.6mA   -21.36mA
-840mV    -18.66mA   -309.5mA   -18.51mA
-810mV    -14.08mA   -161.6mA   -15.94mA
-780mV    -11.38mA   -83.33mA   -13.55mA
-600mV    -3.02mA    -4.329mA   -3.104mA
1.2V      30.28uA    18.17uA    37.27uA
[POWER_clamp]
|Voltage   I(typ)   I(min)   I(max)
-1.2V     127mA      149.4mA    122.2mA
-1.12V    84.97mA    114mA      70.27mA
-1.06V    55.51mA    88.42mA    35.67mA
-1.02V    37.63mA    72.04mA    17.17mA
-1V       29.51mA    64.13mA    10.3mA
-960mV    15.69mA    48.99mA    2.571mA
-900mV    3.624mA    28.77mA    182.8uA
-840mV    490.7uA    13.24mA    11.35uA
-800mV    116.8uA    6.532mA    1.77uA
-740mV    13.2uA     1.724mA    109.1nA
-620mV    167.4nA    79.36uA    0A
0V        0A         17.87nA    0A
[Ramp]
| variable   typ   min   max
dV/dt_r  0.38524/19.47649n   0.12532/48.28787n   0.54787/9.59604n
dV/dt_f  0.37096/22.02737n   92.39400m/55.18950n 0.59419/9.22666n
R_load = 50.000000
[Rising Waveform]
R_fixture= 50.000000
V_fixture= 1.200000
V_fixture_min= 0.900000
V_fixture_max= 1.320000
|time   V(typ)   V(min)   V(max)
0s        581.2mV    745.1mV    329.2mV
2.803ns   581.3mV    745.1mV    367.3mV
3.203ns   581.3mV    745.1mV    512.4mV
3.604ns   580.8mV    745.1mV    959.1mV
4.004ns   579.4mV    745.1mV    1.242V
5.005ns   588.5mV    745.1mV    1.312V
7.007ns   1.115V     745.1mV    1.316V
8.408ns   1.193V     745.1mV    1.316V
23.22ns   1.198V     896.2mV    1.319V
99.7ns    1.2V       899.5mV    1.319V
[Rising Waveform]
R_fixture= 50.000000
V_fixture= 0.0
V_fixture_min= 0.0
V_fixture_max= 0.0
|time   V(typ)   V(min)   V(max)
0s        1.93uV     1.552uV    1.951uV
10.21ns   -990.6uV   -496.1nV   9.235mV
19.22ns   12.33mV    -1.087mV   527.9mV
24.02ns   99.78mV    -1.624mV   751.5mV
28.23ns   203.4mV    -310.6uV   841.1mV
36.04ns   378.3mV    -48.27uV   894.6mV
51.05ns   569.6mV    1.188mV    911.2mV
75.08ns   634.3mV    47.42mV    913.2mV
145.3ns   642mV      191.9mV    913.2mV
299.1ns   642.1mV    209.1mV    913.2mV
[Falling Waveform]
R_fixture= 50.000000
V_fixture= 1.200000
V_fixture_min= 0.900000
V_fixture_max= 1.320000
|time   V(typ)   V(min)   V(max)
0s        1.2V       899.5mV    1.319V
15.62ns   1.199V     899.8mV    1.276V
19.22ns   1.198V     899.9mV    1.132V
25.83ns   1.181V     899.6mV    666.6mV
28.83ns   1.154V     899.4mV    521.4mV
42.64ns   883.6mV    899mV      365.4mV
57.66ns   692.5mV    898.3mV    338mV
84.68ns   603.7mV    871.9mV    329.7mV
153.2ns   581.4mV    767mV      329.2mV
299.1ns   581.2mV    745.1mV    329.2mV
[Falling Waveform]
R_fixture= 50.000000
V_fixture= 0.0
V_fixture_min= 0.0
V_fixture_max= 0.0
|time   V(typ)   V(min)   V(max)
0s        642.1mV    209.1mV    913.2mV
1.522ns   642mV      209.1mV    895mV
2.803ns   655mV      209.1mV    406.1mV
3.283ns   590.2mV    209.1mV    230.3mV
4.885ns   236.4mV    208.7mV    10.78mV
5.926ns   100.1mV    211.2mV    3.243mV
8.168ns   4.016mV    189.1mV    985.2uV
11.85ns   598.7uV    51.46mV    781.2uV
15.22ns   243.2uV    14.65mV    747.5uV
39.88ns   1.93uV     1.552uV    1.951uV
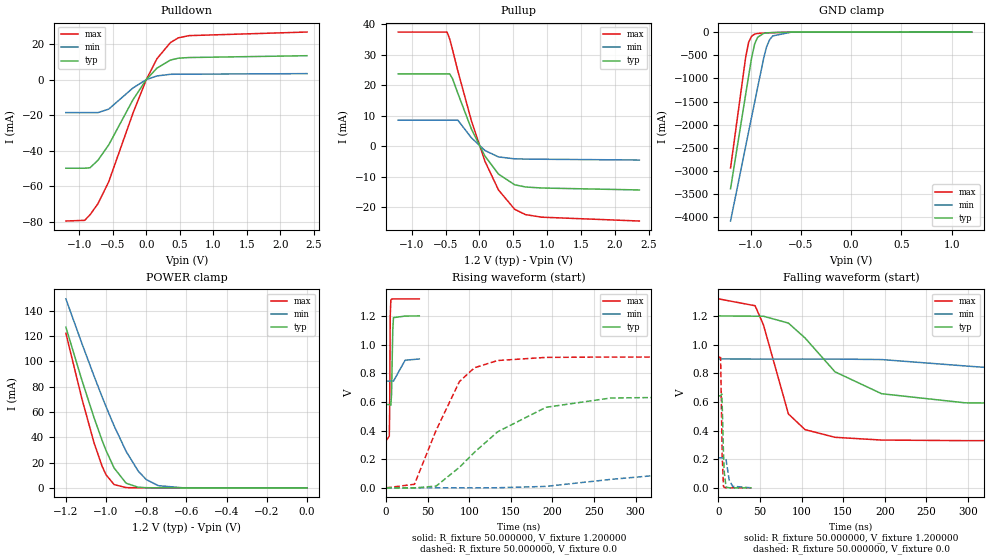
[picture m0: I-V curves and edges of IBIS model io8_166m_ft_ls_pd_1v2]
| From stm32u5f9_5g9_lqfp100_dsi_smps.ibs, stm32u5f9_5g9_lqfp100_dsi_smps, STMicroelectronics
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|   Model io8_166m_ft_ls_pd_1v2
[Model]  io8_166m_ft_ls_pd_1v2
Model_type I/O
Polarity   Non-Inverting
Enable   Active-Low
Vinl =   0.360000V
Vinh =   0.840000V
Vmeas =  0.600000V
Cref =   50.000000pF
Rref =   100.000000M
Vref =   0.0V
C_comp   3.151400pF   3.086700pF   3.197700pF
[Temperature Range]   25.000000   0.140000k   -40.000000
[Pullup Reference]   1.200000V   0.900000V   1.320000V
[Pulldown Reference]   0.0V   0.0V   0.0V
[POWER Clamp Reference]   1.200000V   0.900000V   1.320000V
[GND Clamp Reference]   0.0V   0.0V   0.0V
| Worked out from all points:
|   slope of the pulldown table from 0 to 0.18 V, typ, clamps not added: 25.4 ohm
|   slope of the pullup table from 0 to 0.18 V, typ, clamps not added: 27.8 ohm
|   GND clamp passes 1 mA (typ) near -0.51 V on its own axis
|   POWER clamp passes 1 mA (typ) near -0.86 V on its own axis
|   rising waveform, R_fixture 50.000000, V_fixture 1.200000: 20-80 % time 1.12ns typ, 3.03ns min, 550ps max; typ from 0.581 V to 1.2 V
|   rising waveform, R_fixture 50.000000, V_fixture 0.0: 20-80 % time 83.8ns typ, 204ns min, 40.6ns max; typ from 0 V to 0.642 V
|   falling waveform, R_fixture 50.000000, V_fixture 1.200000: 20-80 % time 70.8ns typ, 188ns min, 28.2ns max; typ from 1.2 V to 0.581 V
|   falling waveform, R_fixture 50.000000, V_fixture 0.0: 20-80 % time 1.99ns typ, 3.69ns min, 1.48ns max; typ from 0.642 V to 0 V
[Pulldown]
|Voltage   I(typ)   I(min)   I(max)
-1.2V     -49.86mA   -18.57mA   -79.56mA
-920mV    -49.86mA   -18.57mA   -79.19mA
-840mV    -49.6mA    -18.57mA   -76.08mA
-720mV    -45.32mA   -18.57mA   -69.74mA
-560mV    -36.71mA   -16.58mA   -57.44mA
-200mV    -11.43mA   -4.74mA    -19.03mA
0V        -10fA      -400fA     0A
160mV     6.477mA    2.075mA    11.78mA
360mV     10.99mA    2.989mA    20.81mA
480mV     12.07mA    3.054mA    23.53mA
640mV     12.43mA    3.074mA    24.76mA
2.4V      13.46mA    3.369mA    26.78mA
[Pullup]
|Voltage   I(typ)   I(min)   I(max)
-1.2V     23.71mA    8.575mA    37.42mA
-480mV    23.71mA    8.575mA    37.42mA
-440mV    23.71mA    8.575mA    35.14mA
-400mV    22.24mA    8.575mA    31.81mA
-320mV    17.36mA    8.575mA    24.69mA
-120mV    5.681mA    2.787mA    8.394mA
80mV      -3.179mA   -1.366mA   -4.88mA
280mV     -9.096mA   -3.479mA   -14.29mA
520mV     -12.61mA   -4.111mA   -20.65mA
680mV     -13.33mA   -4.182mA   -22.38mA
920mV     -13.66mA   -4.239mA   -23.22mA
2.36V     -14.3mA    -4.5mA     -24.47mA
[GND_clamp]
|Voltage   I(typ)   I(min)   I(max)
-1.2V     -3.379A    -4.076A    -2.932A
-1.05V    -1.35A     -2.47A     -550.7mA
-1.02V    -947.8mA   -2.15A     -221.5mA
-990mV    -552.4mA   -1.829A    -88.45mA
-960mV    -255.3mA   -1.51A     -44.89mA
-930mV    -111.8mA   -1.191A    -30.7mA
-870mV    -28.37mA   -564.6mA   -21.36mA
-840mV    -18.66mA   -309.5mA   -18.51mA
-810mV    -14.08mA   -161.6mA   -15.94mA
-780mV    -11.38mA   -83.33mA   -13.55mA
-600mV    -3.02mA    -4.329mA   -3.104mA
1.2V      30.28uA    18.17uA    37.27uA
[POWER_clamp]
|Voltage   I(typ)   I(min)   I(max)
-1.2V     127mA      149.4mA    122.2mA
-1.12V    84.97mA    114mA      70.27mA
-1.06V    55.51mA    88.42mA    35.67mA
-1.02V    37.63mA    72.04mA    17.17mA
-1V       29.51mA    64.13mA    10.3mA
-960mV    15.69mA    48.99mA    2.571mA
-900mV    3.624mA    28.77mA    182.8uA
-840mV    490.7uA    13.24mA    11.35uA
-800mV    116.8uA    6.532mA    1.77uA
-740mV    13.2uA     1.724mA    109.1nA
-620mV    167.4nA    79.36uA    0A
0V        0A         17.87nA    0A
[Ramp]
| variable   typ   min   max
dV/dt_r  0.38522/83.69049n   0.12510/0.20347u   0.54788/40.60537n
dV/dt_f  0.37097/70.78035n   92.35800m/0.18831u  0.59419/28.04893n
R_load = 50.000000
[Rising Waveform]
R_fixture= 50.000000
V_fixture= 1.200000
V_fixture_min= 0.900000
V_fixture_max= 1.320000
|time   V(typ)   V(min)   V(max)
0s        581.2mV    745.1mV    329.2mV
3.764ns   581.3mV    745.1mV    360.6mV
4.244ns   581.3mV    745.1mV    539.6mV
4.885ns   579.8mV    745.1mV    1.194V
5.606ns   576.6mV    745.1mV    1.308V
6.486ns   653mV      745.1mV    1.317V
7.928ns   1.1V       745.1mV    1.318V
8.809ns   1.188V     745.1mV    1.319V
22.82ns   1.199V     890.8mV    1.319V
39.88ns   1.2V       899.5mV    1.319V
[Rising Waveform]
R_fixture= 50.000000
V_fixture= 0.0
V_fixture_min= 0.0
V_fixture_max= 0.0
|time   V(typ)   V(min)   V(max)
0s        1.941nV    235.2nV    1.147nV
34.03ns   -72.4uV    -36.19uV   24.95mV
60.06ns   11.9mV     -31.26uV   401.1mV
88.09ns   143mV      39.09uV    741.5mV
106.1ns   247.8mV    121.5uV    837.9mV
134.1ns   391.3mV    581.1uV    888.7mV
192.2ns   562.1mV    10.01mV    910.5mV
270.3ns   627.2mV    59.05mV    913mV
516.5ns   642mV      184.9mV    913.1mV
997ns     642.1mV    209mV      913.1mV
[Falling Waveform]
R_fixture= 50.000000
V_fixture= 1.200000
V_fixture_min= 0.900000
V_fixture_max= 1.320000
|time   V(typ)   V(min)   V(max)
0s        1.2V       899.5mV    1.319V
44.04ns   1.198V     899.1mV    1.271V
54.05ns   1.198V     899.1mV    1.138V
84.08ns   1.15V      899.1mV    515.7mV
104.1ns   1.046V     899.1mV    406.4mV
140.1ns   809.9mV    898.9mV    352.7mV
196.2ns   656.9mV    895.4mV    333.5mV
296.3ns   593.5mV    851mV      329.4mV
494.5ns   581.3mV    767.4mV    329.2mV
997ns     581.2mV    745.1mV    329.2mV
[Falling Waveform]
R_fixture= 50.000000
V_fixture= 0.0
V_fixture_min= 0.0
V_fixture_max= 0.0
|time   V(typ)   V(min)   V(max)
0s        642.1mV    209mV      913.1mV
2.563ns   642.1mV    209mV      909.1mV
3.924ns   655.8mV    209.1mV    409.1mV
4.404ns   590.8mV    209.1mV    234.2mV
6.006ns   238.4mV    208.7mV    10.35mV
7.047ns   102.7mV    211.2mV    2.57mV
9.129ns   5.155mV    195.3mV    313.8uV
12.89ns   421.9uV    53.99mV    -76.59uV
16.98ns   23.77uV    11.05mV    -77.82uV
39.88ns   1.941nV    235.2nV    1.147nV
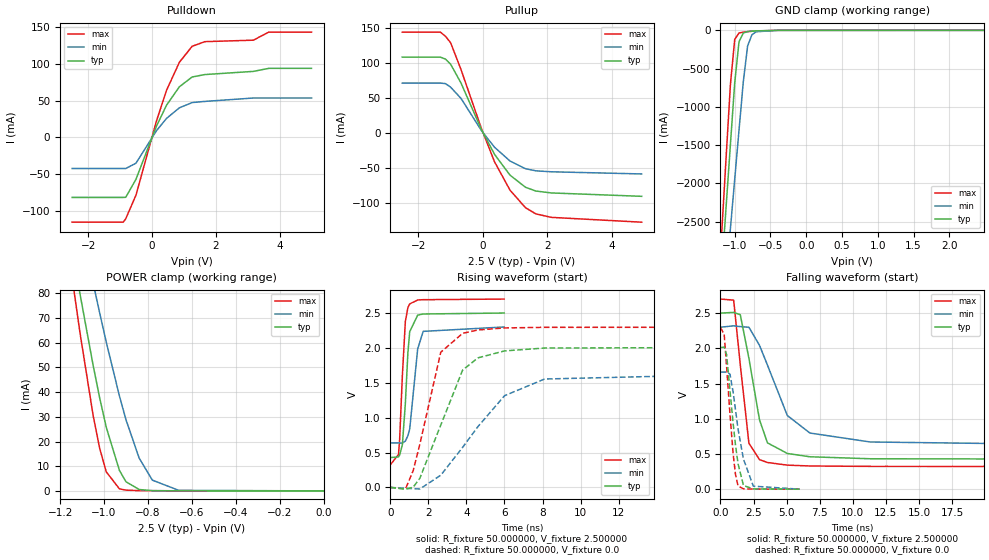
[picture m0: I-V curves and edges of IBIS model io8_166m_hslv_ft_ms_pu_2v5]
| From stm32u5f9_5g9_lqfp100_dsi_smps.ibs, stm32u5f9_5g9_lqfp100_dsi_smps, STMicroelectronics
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|   Model io8_166m_hslv_ft_ms_pu_2v5
[Model]  io8_166m_hslv_ft_ms_pu_2v5
Model_type I/O
Polarity   Non-Inverting
Enable   Active-Low
Vinl =   0.750000V
Vinh =   1.750000V
Vmeas =  1.250000V
Cref =   50.000000pF
Rref =   100.000000M
Vref =   0.0V
C_comp   3.458600pF   3.458000pF   3.495600pF
[Temperature Range]   25.000000   0.140000k   -40.000000
[Pullup Reference]   2.500000V   2.300000V   2.700000V
[Pulldown Reference]   0.0V   0.0V   0.0V
[POWER Clamp Reference]   2.500000V   2.300000V   2.700000V
[GND Clamp Reference]   0.0V   0.0V   0.0V
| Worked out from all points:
|   slope of the pulldown table from 0 to 0.375 V, typ, clamps not added: 10.1 ohm
|   slope of the pullup table from 0 to 0.375 V, typ, clamps not added: 11.7 ohm
|   GND clamp passes 1 mA (typ) near -0.50 V on its own axis
|   POWER clamp passes 1 mA (typ) near -0.85 V on its own axis
|   rising waveform, R_fixture 50.000000, V_fixture 2.500000: 20-80 % time 250ps typ, 331ps min, 233ps max; typ from 0.428 V to 2.5 V
|   rising waveform, R_fixture 50.000000, V_fixture 0.0: 20-80 % time 1.64ns typ, 2.94ns min, 1.12ns max; typ from 0 V to 2.01 V
|   falling waveform, R_fixture 50.000000, V_fixture 2.500000: 20-80 % time 1.17ns typ, 2.21ns min, 750ps max; typ from 2.5 V to 0.428 V
|   falling waveform, R_fixture 50.000000, V_fixture 0.0: 20-80 % time 668ps typ, 870ps min, 544ps max; typ from 2.01 V to 0 V
[Pulldown]
|Voltage   I(typ)   I(min)   I(max)
-2.5V     -81.62mA   -42.31mA   -115.3mA
-900mV    -81.62mA   -42.31mA   -115.3mA
-820mV    -81.43mA   -42.31mA   -110.6mA
-500mV    -56.95mA   -35.08mA   -78.57mA
140mV     15.18mA    9.02mA     22.02mA
460mV     44mA       25.98mA    64.38mA
860mV     68.91mA    40.27mA    102.2mA
1.26V     82.21mA    47.42mA    124mA
1.66V     85.54mA    49mA       130.3mA
3.18V     89.84mA    53.62mA    132.3mA
3.66V     93.97mA    53.62mA    143.3mA
5V        93.97mA    53.62mA    143.3mA
[Pullup]
|Voltage   I(typ)   I(min)   I(max)
-2.5V     108.1mA    71.01mA    143.9mA
-1.32V    108.1mA    71.01mA    143.9mA
-1.16V    105.3mA    70.19mA    137.9mA
-1V       97.92mA    65.1mA     128.6mA
-680mV    71.17mA    49.13mA    90.44mA
-40mV     3.893mA    2.628mA    5.181mA
360mV     -30.97mA   -20.78mA   -41.56mA
840mV     -60.71mA   -40.52mA   -82.21mA
1.32V     -78.06mA   -51.54mA   -107.3mA
1.64V     -83.42mA   -54.54mA   -116.1mA
2.12V     -86.16mA   -55.91mA   -121.1mA
4.92V     -91mA      -59mA      -128mA
[GND_clamp]
|Voltage   I(typ)   I(min)   I(max)
-2.5V     -9.641A    -9.693A    -9.352A
-1.18V    -3.114A    -3.874A    -2.614A
-1.12V    -2.301A    -3.23A     -1.656A
-1.06V    -1.489A    -2.587A    -706.2mA
-1V       -685.8mA   -1.945A    -119.3mA
-940mV    -149.7mA   -1.304A    -34.73mA
-880mV    -35.54mA   -672.6mA   -23.06mA
-820mV    -16.2mA    -206.4mA   -17.27mA
-760mV    -10.58mA   -57.55mA   -12.41mA
-700mV    -7.152mA   -18.74mA   -8.24mA
-400mV    -103.3uA   -378.6uA   -41.75uA
2.48V     0A         13.22nA    0A
[POWER_clamp]
|Voltage   I(typ)   I(min)   I(max)
-2.49V    881.1mA    773.1mA    1.07A
-1.14V    95.32mA    122.8mA    82.93mA
-1.11V    79.97mA    109.7mA    64.26mA
-1.05V    50.95mA    84.3mA     30.69mA
-1.02V    37.7mA     72.08mA    17.29mA
-990mV    25.79mA    60.29mA    7.738mA
-930mV    8.312mA    38.47mA    853.1uA
-900mV    3.712mA    28.81mA    313.6uA
-840mV    566.2uA    13.29mA    123.7uA
-780mV    119uA      4.365mA    94.04uA
-660mV    38.98uA    251.5uA    57.76uA
0V        0A         18.93nA    0A
[Ramp]
| variable   typ   min   max
dV/dt_r  1.20644/1.63939n   0.99759/2.93170n   1.37763/1.12021n
dV/dt_f  1.24313/1.16638n   0.99674/2.20741n   1.42608/0.74895n
R_load = 50.000000
[Rising Waveform]
R_fixture= 50.000000
V_fixture= 2.500000
V_fixture_min= 2.300000
V_fixture_max= 2.700000
|time   V(typ)   V(min)   V(max)
0s        428.1mV    638.1mV    323.2mV
432.4ps   437.6mV    638.1mV    473.1mV
492.5ps   465.5mV    637.7mV    690.1mV
636.6ps   612.8mV    634.3mV    1.607V
792.8ps   1.204V     664.7mV    2.38V
924.9ps   1.927V     741mV      2.575V
1.021ns   2.232V     836.2mV    2.631V
1.441ns   2.47V      1.987V     2.687V
1.73ns    2.486V     2.237V     2.691V
5.982ns   2.5V       2.3V       2.7V
[Rising Waveform]
R_fixture= 50.000000
V_fixture= 0.0
V_fixture_min= 0.0
V_fixture_max= 0.0
|time   V(typ)   V(min)   V(max)
0s        420.7uV    545.8uV    461.3uV
800.8ps   -24.65mV   -12.94mV   -20.63mV
1.201ns   2.863mV    -17.83mV   238.5mV
1.552ns   130.6mV    -21.85mV   617.4mV
2.653ns   894.3mV    175.2mV    1.938V
3.804ns   1.683V     575.3mV    2.209V
4.605ns   1.857V     871.6mV    2.257V
6.006ns   1.957V     1.315V     2.286V
8.108ns   1.998V     1.554V     2.295V
24.92ns   2.011V     1.663V     2.296V
[Falling Waveform]
R_fixture= 50.000000
V_fixture= 2.500000
V_fixture_min= 2.300000
V_fixture_max= 2.700000
|time   V(typ)   V(min)   V(max)
0s        2.5V       2.3V       2.7V
1.001ns   2.511V     2.32V      2.685V
1.502ns   2.478V     2.309V     1.767V
2.152ns   1.859V     2.3V       653.6mV
2.953ns   985.4mV    2.043V     419.8mV
3.554ns   658.1mV    1.762V     379.1mV
5.055ns   507.3mV    1.046V     341.7mV
6.757ns   460.5mV    797.7mV    329.6mV
11.31ns   432.3mV    670.6mV    323.7mV
24.92ns   428.1mV    638.1mV    323.2mV
[Falling Waveform]
R_fixture= 50.000000
V_fixture= 0.0
V_fixture_min= 0.0
V_fixture_max= 0.0
|time   V(typ)   V(min)   V(max)
0s        2.011V     1.663V     2.296V
288.3ps   2.018V     1.663V     2.198V
468.5ps   1.911V     1.663V     1.744V
720.7ps   1.405V     1.636V     1.069V
961ps     936.6mV    1.379V     506.4mV
1.141ns   623.2mV    1.126V     208.1mV
1.333ns   360.2mV    853.2mV    45.16mV
1.742ns   52.47mV    426.3mV    4.914mV
2.486ns   4.17mV     42.89mV    2.13mV
5.982ns   420.7uV    545.8uV    461.3uV
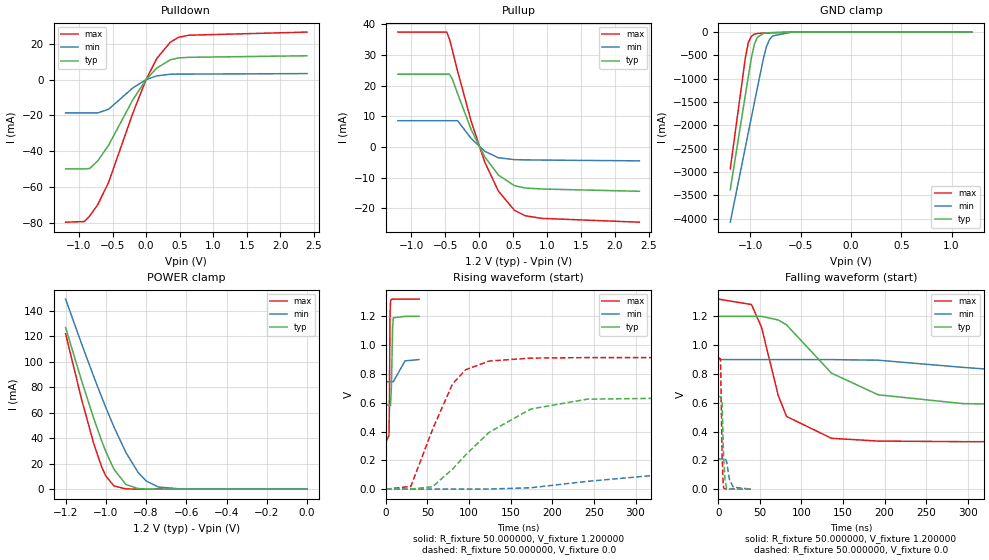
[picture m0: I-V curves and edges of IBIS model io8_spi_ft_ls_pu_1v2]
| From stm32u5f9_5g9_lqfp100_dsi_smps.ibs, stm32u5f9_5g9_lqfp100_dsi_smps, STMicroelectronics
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|   Model io8_spi_ft_ls_pu_1v2
[Model]  io8_spi_ft_ls_pu_1v2
Model_type I/O
Polarity   Non-Inverting
Enable   Active-Low
Vinl =   0.360000V
Vinh =   0.840000V
Vmeas =  0.600000V
Cref =   50.000000pF
Rref =   100.000000M
Vref =   0.0V
C_comp   3.132800pF   3.069700pF   3.178000pF
[Temperature Range]   25.000000   0.140000k   -40.000000
[Pullup Reference]   1.200000V   0.900000V   1.320000V
[Pulldown Reference]   0.0V   0.0V   0.0V
[POWER Clamp Reference]   1.200000V   0.900000V   1.320000V
[GND Clamp Reference]   0.0V   0.0V   0.0V
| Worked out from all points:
|   slope of the pulldown table from 0 to 0.18 V, typ, clamps not added: 25.4 ohm
|   slope of the pullup table from 0 to 0.18 V, typ, clamps not added: 27.8 ohm
|   GND clamp passes 1 mA (typ) near -0.51 V on its own axis
|   POWER clamp passes 1 mA (typ) near -0.86 V on its own axis
|   rising waveform, R_fixture 50.000000, V_fixture 1.200000: 20-80 % time 1.25ns typ, 3.35ns min, 597ps max; typ from 0.583 V to 1.2 V
|   rising waveform, R_fixture 50.000000, V_fixture 0.0: 20-80 % time 77.8ns typ, 194ns min, 37.8ns max; typ from 0 V to 0.643 V
|   falling waveform, R_fixture 50.000000, V_fixture 1.200000: 20-80 % time 69.8ns typ, 185ns min, 27.7ns max; typ from 1.2 V to 0.583 V
|   falling waveform, R_fixture 50.000000, V_fixture 0.0: 20-80 % time 2.24ns typ, 4.29ns min, 1.61ns max; typ from 0.643 V to 0 V
[Pulldown]
|Voltage   I(typ)   I(min)   I(max)
-1.2V     -49.85mA   -18.57mA   -79.56mA
-920mV    -49.85mA   -18.57mA   -79.19mA
-840mV    -49.59mA   -18.57mA   -76.08mA
-720mV    -45.32mA   -18.57mA   -69.73mA
-560mV    -36.71mA   -16.58mA   -57.44mA
-200mV    -11.43mA   -4.739mA   -19.03mA
0V        0A         0A         0A
160mV     6.476mA    2.074mA    11.78mA
360mV     10.99mA    2.988mA    20.81mA
480mV     12.07mA    3.052mA    23.52mA
640mV     12.42mA    3.073mA    24.76mA
2.4V      13.3mA     3.33mA     26.5mA
[Pullup]
|Voltage   I(typ)   I(min)   I(max)
-1.2V     23.7mA     8.568mA    37.41mA
-480mV    23.7mA     8.568mA    37.41mA
-440mV    23.7mA     8.568mA    35.14mA
-400mV    22.24mA    8.568mA    31.81mA
-320mV    17.36mA    8.568mA    24.69mA
-120mV    5.681mA    2.787mA    8.394mA
80mV      -3.179mA   -1.366mA   -4.88mA
280mV     -9.096mA   -3.48mA    -14.29mA
520mV     -12.61mA   -4.111mA   -20.65mA
680mV     -13.33mA   -4.182mA   -22.38mA
920mV     -13.66mA   -4.239mA   -23.22mA
2.36V     -14.4mA    -4.5mA     -24.46mA
[GND_clamp]
|Voltage   I(typ)   I(min)   I(max)
-1.2V     -3.379A    -4.076A    -2.932A
-1.05V    -1.35A     -2.47A     -550.7mA
-1.02V    -947.8mA   -2.149A    -221.5mA
-990mV    -552.4mA   -1.829A    -88.44mA
-960mV    -255.3mA   -1.51A     -44.87mA
-930mV    -111.8mA   -1.191A    -30.68mA
-870mV    -28.35mA   -564.6mA   -21.34mA
-840mV    -18.65mA   -309.5mA   -18.49mA
-810mV    -14.07mA   -161.6mA   -15.92mA
-780mV    -11.37mA   -83.33mA   -13.53mA
-600mV    -3.009mA   -4.321mA   -3.091mA
1.2V      0A         13.65nA    0A
[POWER_clamp]
|Voltage   I(typ)   I(min)   I(max)
-1.2V     127mA      149.4mA    122.2mA
-1.12V    84.98mA    114mA      70.29mA
-1.06V    55.52mA    88.42mA    35.69mA
-1.02V    37.64mA    72.04mA    17.19mA
-1V       29.52mA    64.13mA    10.33mA
-960mV    15.7mA     48.99mA    2.596mA
-900mV    3.636mA    28.77mA    207.8uA
-840mV    502.9uA    13.24mA    43.56uA
-800mV    129uA      6.535mA    43.56uA
-740mV    25.5uA     1.726mA    43.56uA
-620mV    25.17uA    82.33uA    36.06uA
0V        0A         17.36nA    0A
[Ramp]
| variable   typ   min   max
dV/dt_r  0.38569/77.78044n   0.12548/0.19387u   0.54818/37.78619n
dV/dt_f  0.37036/69.71707n   92.09400m/0.18565u  0.59402/27.69724n
R_load = 50.000000
[Rising Waveform]
R_fixture= 50.000000
V_fixture= 1.200000
V_fixture_min= 0.900000
V_fixture_max= 1.320000
|time   V(typ)   V(min)   V(max)
0s        582.7mV    746.1mV    330mV
3.764ns   582.9mV    746.1mV    372.3mV
4.244ns   582.7mV    746.1mV    557.9mV
4.885ns   580.6mV    746.1mV    1.178V
5.606ns   579.9mV    746.1mV    1.308V
6.647ns   707.8mV    746.1mV    1.318V
8.088ns   1.12V      746.1mV    1.319V
8.969ns   1.19V      746.1mV    1.32V
23.06ns   1.2V       891.1mV    1.32V
39.88ns   1.2V       900mV      1.32V
[Rising Waveform]
R_fixture= 50.000000
V_fixture= 0.0
V_fixture_min= 0.0
V_fixture_max= 0.0
|time   V(typ)   V(min)   V(max)
0s        434.2uV    495.9uV    378.8uV
30.03ns   1.365mV    729.4uV    19.76mV
56.06ns   17.12mV    894.6uV    414.9mV
80.08ns   139.4mV    964.3uV    731.1mV
96.1ns    239.8mV    1.036mV    830mV
124.1ns   395mV      1.451mV    889.7mV
174.2ns   557.1mV    10.1mV     910.2mV
242.2ns   625.3mV    54.72mV    913.8mV
510.5ns   643.3mV    192.4mV    914mV
997ns     643.3mV    210mV      914mV
[Falling Waveform]
R_fixture= 50.000000
V_fixture= 1.200000
V_fixture_min= 0.900000
V_fixture_max= 1.320000
|time   V(typ)   V(min)   V(max)
0s        1.2V       900mV      1.32V
40.04ns   1.2V       900.1mV    1.282V
52.05ns   1.2V       900mV      1.124V
72.07ns   1.175V     900mV      651.8mV
82.08ns   1.141V     900mV      505.3mV
136.1ns   805.9mV    899.7mV    353.5mV
192.2ns   655.6mV    895.6mV    334.2mV
294.3ns   593.9mV    845.7mV    330.2mV
476.5ns   582.8mV    769.1mV    330mV
997ns     582.7mV    746.1mV    330mV
[Falling Waveform]
R_fixture= 50.000000
V_fixture= 0.0
V_fixture_min= 0.0
V_fixture_max= 0.0
|time   V(typ)   V(min)   V(max)
0s        643.3mV    210mV      914mV
2.803ns   643mV      210mV      905.5mV
4.645ns   613mV      210mV      258mV
5.606ns   403.9mV    209.7mV    79.55mV
6.486ns   226.2mV    209.9mV    9.679mV
8.168ns   67.52mV    216.8mV    2.156mV
10.17ns   3.238mV    190.6mV    948uV
13.53ns   1.01mV     66.85mV    639.2uV
18.18ns   475.6uV    13.83mV    624.7uV
39.88ns   434.2uV    495.9uV    378.8uV
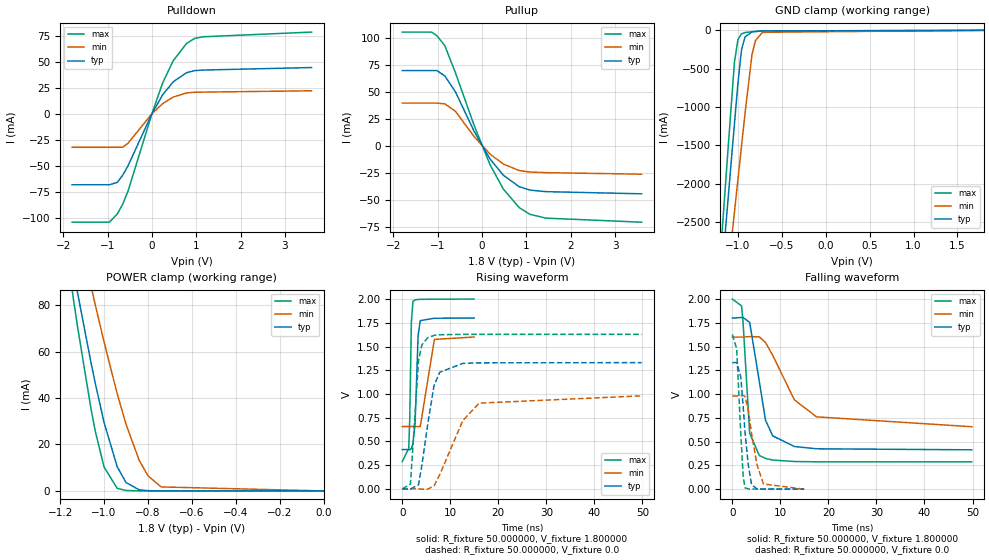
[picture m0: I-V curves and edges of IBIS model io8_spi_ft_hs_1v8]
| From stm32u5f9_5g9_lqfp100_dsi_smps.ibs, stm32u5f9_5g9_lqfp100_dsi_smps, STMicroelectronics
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|   Model io8_spi_ft_hs_1v8
[Model]  io8_spi_ft_hs_1v8
Model_type I/O
Polarity   Non-Inverting
Enable   Active-Low
Vinl =   0.540000V
Vinh =   1.260000V
Vmeas =  0.900000V
Cref =   50.000000pF
Rref =   100.000000M
Vref =   0.0V
C_comp   3.338500pF   3.332300pF   3.378900pF
[Temperature Range]   25.000000   0.140000k   -40.000000
[Pullup Reference]   1.800000V   1.600000V   2.000000V
[Pulldown Reference]   0.0V   0.0V   0.0V
[POWER Clamp Reference]   1.800000V   1.600000V   2.000000V
[GND Clamp Reference]   0.0V   0.0V   0.0V
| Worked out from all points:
|   slope of the pulldown table from 0 to 0.27 V, typ, clamps not added: 13.6 ohm
|   slope of the pullup table from 0 to 0.27 V, typ, clamps not added: 15.9 ohm
|   GND clamp passes 1 mA (typ) near -0.51 V on its own axis
|   POWER clamp passes 1 mA (typ) near -0.86 V on its own axis
|   rising waveform, R_fixture 50.000000, V_fixture 1.800000: 20-80 % time 534ps typ, 1.08ns min, 336ps max; typ from 0.414 V to 1.8 V
|   rising waveform, R_fixture 50.000000, V_fixture 0.0: 20-80 % time 2.36ns typ, 5.18ns min, 1.21ns max; typ from 0 V to 1.33 V
|   falling waveform, R_fixture 50.000000, V_fixture 1.800000: 20-80 % time 2.6ns typ, 6.25ns min, 1.18ns max; typ from 1.8 V to 0.414 V
|   falling waveform, R_fixture 50.000000, V_fixture 0.0: 20-80 % time 1.33ns typ, 1.97ns min, 905ps max; typ from 1.33 V to 0 V
[Pulldown]
|Voltage   I(typ)   I(min)   I(max)
-1.8V     -68.38mA   -32.32mA   -104.4mA
-960mV    -68.38mA   -32.32mA   -104.4mA
-780mV    -66.07mA   -32.32mA   -96.42mA
-660mV    -59.2mA    -32.31mA   -87.22mA
-540mV    -50.22mA   -28.51mA   -74.66mA
0V        0A         -300fA     0A
240mV     18.04mA    9.599mA    29.42mA
480mV     30.68mA    16.02mA    50.95mA
780mV     39.47mA    19.98mA    67.56mA
960mV     41.44mA    20.62mA    72.37mA
1.14V     41.99mA    20.78mA    74.01mA
3.6V      44.44mA    22.06mA    78.55mA
[Pullup]
|Voltage   I(typ)   I(min)   I(max)
-1.8V     70.06mA    39.89mA    105.7mA
-1.14V    70.06mA    39.89mA    105.7mA
-1.02V    70.06mA    39.89mA    102.4mA
-840mV    65.11mA    39.14mA    93.15mA
-600mV    50.32mA    32.31mA    68.01mA
-180mV    13.77mA    8.913mA    19.32mA
180mV     -11.9mA    -7.442mA   -17.26mA
480mV     -26.98mA   -16.65mA   -39.76mA
840mV     -37.65mA   -22.63mA   -57.07mA
1.08V     -40.74mA   -24.01mA   -63.22mA
1.44V     -42.19mA   -24.58mA   -66.73mA
3.6V      -44.2mA    -26mA      -70.5mA
[GND_clamp]
|Voltage   I(typ)   I(min)   I(max)
-1.8V     -9.908A    -9.683A    -9.994A
-1.2V     -3.383A    -4.084A    -2.934A
-1.16V    -2.841A    -3.655A    -2.294A
-1.12V    -2.299A    -3.226A    -1.656A
-1.04V    -1.218A    -2.369A    -414.2mA
-1V       -684.7mA   -1.941A    -119.2mA
-960mV    -257.2mA   -1.514A    -45.66mA
-920mV    -87.03mA   -1.089A    -28.93mA
-840mV    -19.35mA   -312.8mA   -18.96mA
-800mV    -13.55mA   -132.4mA   -15.49mA
-720mV    -8.042mA   -25.66mA   -9.49mA
1.8V      0A         13.64nA    0A
[POWER_clamp]
|Voltage   I(typ)   I(min)   I(max)
-1.8V     470.8mA    433.7mA    554.6mA
-1.14V    95.25mA    122.7mA    82.82mA
-1.12V    84.97mA    114mA      70.27mA
-1.06V    55.51mA    88.42mA    35.67mA
-1.04V    46.34mA    80.15mA    25.76mA
-1V       29.51mA    64.13mA    10.3mA
-940mV    10.39mA    41.86mA    1.109mA
-900mV    3.624mA    28.77mA    182.8uA
-840mV    490.7uA    13.24mA    11.35uA
-800mV    116.8uA    6.532mA    1.77uA
-740mV    13.2uA     1.724mA    109.3nA
0V        0A         18.75nA    0A
[Ramp]
| variable   typ   min   max
dV/dt_r  0.79770/2.36159n   0.58815/5.17394n   0.97668/1.21258n
dV/dt_f  0.83162/2.59219n   0.56549/6.24151n   1.02769/1.17980n
R_load = 50.000000
[Rising Waveform]
R_fixture= 50.000000
V_fixture= 1.800000
V_fixture_min= 1.600000
V_fixture_max= 2.000000
|time   V(typ)   V(min)   V(max)
0s        414mV      656.9mV    287.2mV
1.351ns   413.3mV    656.9mV    427.7mV
1.562ns   412.3mV    656.9mV    736.4mV
1.892ns   422.7mV    656.9mV    1.748V
2.222ns   474.2mV    656.9mV    1.974V
2.673ns   691.7mV    656.7mV    1.992V
3.303ns   1.617V     655.2mV    1.996V
3.754ns   1.773V     657.5mV    1.997V
6.697ns   1.798V     1.575V     1.999V
14.95ns   1.8V       1.6V       2V
[Rising Waveform]
R_fixture= 50.000000
V_fixture= 0.0
V_fixture_min= 0.0
V_fixture_max= 0.0
|time   V(typ)   V(min)   V(max)
0s        1.365uV    2.261uV    4.638uV
1.702ns   -2.135mV   110.8nV    49.59mV
3.403ns   43.96mV    -269.2uV   1.358V
4.104ns   255.2mV    -3.343mV   1.518V
5.305ns   680.6mV    -3.258mV   1.593V
6.607ns   1.087V     30.63mV    1.617V
7.808ns   1.229V     149mV      1.624V
12.61ns   1.322V     720mV      1.628V
16.02ns   1.328V     903.2mV    1.628V
49.85ns   1.33V      980.3mV    1.628V
[Falling Waveform]
R_fixture= 50.000000
V_fixture= 1.800000
V_fixture_min= 1.600000
V_fixture_max= 2.000000
|time   V(typ)   V(min)   V(max)
0s        1.8V       1.6V       2V
1.902ns   1.806V     1.6V       1.929V
2.202ns   1.806V     1.6V       1.775V
3.604ns   1.755V     1.605V     587.2mV
5.606ns   1.133V     1.602V     354.7mV
6.907ns   724.6mV    1.542V     323.2mV
8.408ns   560.3mV    1.407V     306.5mV
12.91ns   449mV      939.7mV    290.9mV
17.52ns   424.7mV    761mV      287.9mV
49.85ns   414mV      656.9mV    287.2mV
[Falling Waveform]
R_fixture= 50.000000
V_fixture= 0.0
V_fixture_min= 0.0
V_fixture_max= 0.0
|time   V(typ)   V(min)   V(max)
0s        1.33V      980.3mV    1.628V
900.9ps   1.333V     980.3mV    1.476V
1.742ns   1.183V     980.9mV    586.9mV
2.252ns   868.2mV    986.1mV    135.9mV
2.613ns   612.2mV    974.7mV    15.41mV
3.273ns   270mV      846.9mV    2.791mV
3.994ns   46.87mV    585.9mV    1.426mV
5.105ns   3.157mV    260.8mV    801.5uV
6.486ns   1.219mV    53.8mV     468.2uV
14.95ns   1.365uV    2.261uV    4.638uV
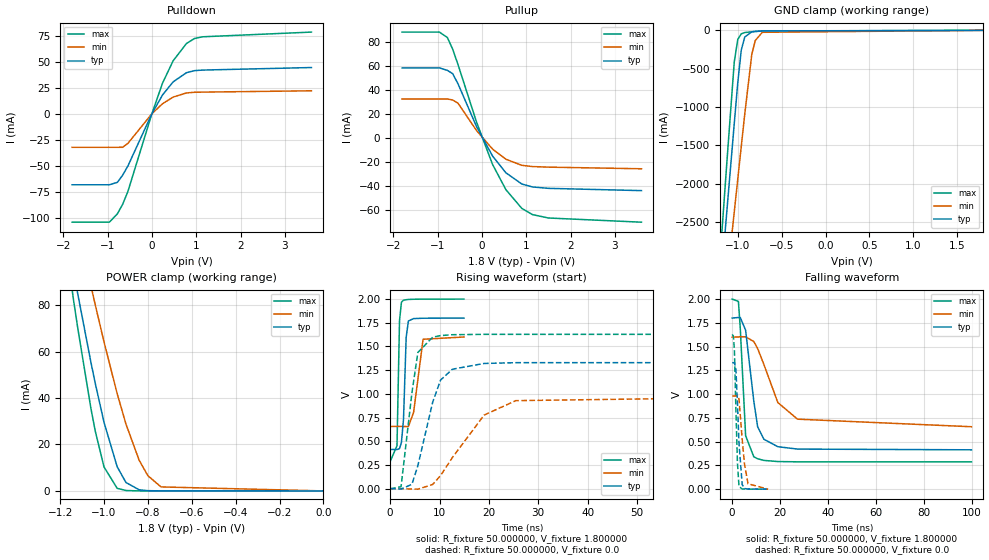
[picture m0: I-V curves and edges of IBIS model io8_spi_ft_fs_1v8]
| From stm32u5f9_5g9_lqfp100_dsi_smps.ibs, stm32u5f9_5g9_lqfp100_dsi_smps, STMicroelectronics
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|   Model io8_spi_ft_fs_1v8
[Model]  io8_spi_ft_fs_1v8
Model_type I/O
Polarity   Non-Inverting
Enable   Active-Low
Vinl =   0.540000V
Vinh =   1.260000V
Vmeas =  0.900000V
Cref =   50.000000pF
Rref =   100.000000M
Vref =   0.0V
C_comp   3.338500pF   3.332300pF   3.378900pF
[Temperature Range]   25.000000   0.140000k   -40.000000
[Pullup Reference]   1.800000V   1.600000V   2.000000V
[Pulldown Reference]   0.0V   0.0V   0.0V
[POWER Clamp Reference]   1.800000V   1.600000V   2.000000V
[GND Clamp Reference]   0.0V   0.0V   0.0V
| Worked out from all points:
|   slope of the pulldown table from 0 to 0.27 V, typ, clamps not added: 13.6 ohm
|   slope of the pullup table from 0 to 0.27 V, typ, clamps not added: 15.9 ohm
|   GND clamp passes 1 mA (typ) near -0.51 V on its own axis
|   POWER clamp passes 1 mA (typ) near -0.86 V on its own axis
|   rising waveform, R_fixture 50.000000, V_fixture 1.800000: 20-80 % time 509ps typ, 1.05ns min, 328ps max; typ from 0.414 V to 1.8 V
|   rising waveform, R_fixture 50.000000, V_fixture 0.0: 20-80 % time 3.77ns typ, 8.23ns min, 1.98ns max; typ from 0 V to 1.33 V
|   falling waveform, R_fixture 50.000000, V_fixture 1.800000: 20-80 % time 3.8ns typ, 9.12ns min, 1.94ns max; typ from 1.8 V to 0.414 V
|   falling waveform, R_fixture 50.000000, V_fixture 0.0: 20-80 % time 1.37ns typ, 2.03ns min, 1ns max; typ from 1.33 V to 0 V
[Pulldown]
|Voltage   I(typ)   I(min)   I(max)
-1.8V     -68.38mA   -32.32mA   -104.4mA
-960mV    -68.38mA   -32.32mA   -104.4mA
-780mV    -66.07mA   -32.32mA   -96.42mA
-660mV    -59.2mA    -32.31mA   -87.22mA
-540mV    -50.22mA   -28.51mA   -74.66mA
0V        0A         -300fA     0A
240mV     18.04mA    9.599mA    29.42mA
480mV     30.68mA    16.02mA    50.95mA
780mV     39.47mA    19.98mA    67.56mA
960mV     41.44mA    20.62mA    72.37mA
1.14V     41.99mA    20.78mA    74.01mA
3.6V      44.44mA    22.06mA    78.55mA
[Pullup]
|Voltage   I(typ)   I(min)   I(max)
-1.8V     58.04mA    32.12mA    87.86mA
-960mV    58.04mA    32.12mA    87.86mA
-780mV    55.99mA    32.12mA    83.36mA
-660mV    53.21mA    31.29mA    73.65mA
-540mV    44.81mA    28.64mA    60.84mA
-120mV    9.014mA    5.781mA    12.75mA
240mV     -15.38mA   -9.6mA     -22.37mA
540mV     -29.31mA   -18.02mA   -43.36mA
900mV     -38.69mA   -23.13mA   -58.99mA
1.14V     -41.14mA   -24.16mA   -64.17mA
1.5V      -42.31mA   -24.64mA   -67mA
3.6V      -44.2mA    -26mA      -70.5mA
[GND_clamp]
|Voltage   I(typ)   I(min)   I(max)
-1.8V     -9.908A    -9.683A    -9.994A
-1.2V     -3.383A    -4.084A    -2.934A
-1.16V    -2.841A    -3.655A    -2.294A
-1.12V    -2.299A    -3.226A    -1.656A
-1.04V    -1.218A    -2.369A    -414.2mA
-1V       -684.7mA   -1.941A    -119.2mA
-960mV    -257.2mA   -1.514A    -45.66mA
-920mV    -87.03mA   -1.089A    -28.93mA
-840mV    -19.35mA   -312.8mA   -18.96mA
-800mV    -13.55mA   -132.4mA   -15.49mA
-720mV    -8.042mA   -25.66mA   -9.49mA
1.8V      0A         13.64nA    0A
[POWER_clamp]
|Voltage   I(typ)   I(min)   I(max)
-1.8V     470.8mA    433.7mA    554.6mA
-1.14V    95.25mA    122.7mA    82.82mA
-1.12V    84.97mA    114mA      70.27mA
-1.06V    55.51mA    88.42mA    35.67mA
-1.04V    46.34mA    80.15mA    25.76mA
-1V       29.51mA    64.13mA    10.3mA
-940mV    10.39mA    41.86mA    1.109mA
-900mV    3.624mA    28.77mA    182.8uA
-840mV    490.7uA    13.24mA    11.35uA
-800mV    116.8uA    6.532mA    1.77uA
-740mV    13.2uA     1.724mA    109.3nA
0V        0A         18.75nA    0A
[Ramp]
| variable   typ   min   max
dV/dt_r  0.79776/3.76187n   0.58817/8.22044n   0.97668/1.97625n
dV/dt_f  0.83162/3.79430n   0.56587/9.10002n   1.02769/1.93762n
R_load = 50.000000
[Rising Waveform]
R_fixture= 50.000000
V_fixture= 1.800000
V_fixture_min= 1.600000
V_fixture_max= 2.000000
|time   V(typ)   V(min)   V(max)
0s        414mV      656.9mV    287.2mV
1.381ns   413.1mV    656.9mV    452.8mV
1.892ns   423mV      656.9mV    1.772V
2.282ns   488.5mV    656.9mV    1.967V
2.703ns   734.5mV    656.7mV    1.989V
3.243ns   1.598V     655.3mV    1.993V
3.694ns   1.769V     656.1mV    1.996V
4.745ns   1.794V     804.6mV    1.998V
6.667ns   1.798V     1.576V     1.999V
14.95ns   1.8V       1.6V       2V
[Rising Waveform]
R_fixture= 50.000000
V_fixture= 0.0
V_fixture_min= 0.0
V_fixture_max= 0.0
|time   V(typ)   V(min)   V(max)
0s        2.135uV    2.37uV     264.4nV
2.202ns   -3.959mV   1.961uV    20.56mV
4.404ns   46.45mV    -3.235mV   1.01V
5.606ns   242.3mV    -4.856mV   1.437V
8.609ns   911.6mV    44.53mV    1.598V
10.21ns   1.146V     138.9mV    1.615V
12.61ns   1.26V      329mV      1.624V
19.02ns   1.321V     776mV      1.628V
25.43ns   1.329V     928.7mV    1.628V
99.7ns    1.33V      980.3mV    1.628V
[Falling Waveform]
R_fixture= 50.000000
V_fixture= 1.800000
V_fixture_min= 1.600000
V_fixture_max= 2.000000
|time   V(typ)   V(min)   V(max)
0s        1.8V       1.6V       2V
2.603ns   1.806V     1.601V     1.975V
3.403ns   1.804V     1.604V     1.68V
5.606ns   1.672V     1.603V     561.8mV
9.009ns   926.8mV    1.553V     341mV
10.61ns   656.4mV    1.48V      319.8mV
13.21ns   525.4mV    1.312V     302.6mV
19.02ns   446.8mV    911.3mV    290.5mV
27.23ns   421.6mV    736.4mV    287.7mV
99.7ns    414mV      656.9mV    287.2mV
[Falling Waveform]
R_fixture= 50.000000
V_fixture= 0.0
V_fixture_min= 0.0
V_fixture_max= 0.0
|time   V(typ)   V(min)   V(max)
0s        1.33V      980.3mV    1.628V
510.5ps   1.329V     980.3mV    1.611V
930.9ps   1.334V     980.3mV    1.462V
1.562ns   1.255V     980.2mV    830.4mV
2.192ns   909.1mV    986.6mV    278.4mV
2.853ns   481mV      945.9mV    27.56mV
4.174ns   47.82mV    524mV      2.175mV
5.135ns   6.211mV    264.7mV    1.097mV
6.607ns   1.921mV    56.67mV    582.8uV
14.95ns   2.135uV    2.37uV     264.4nV
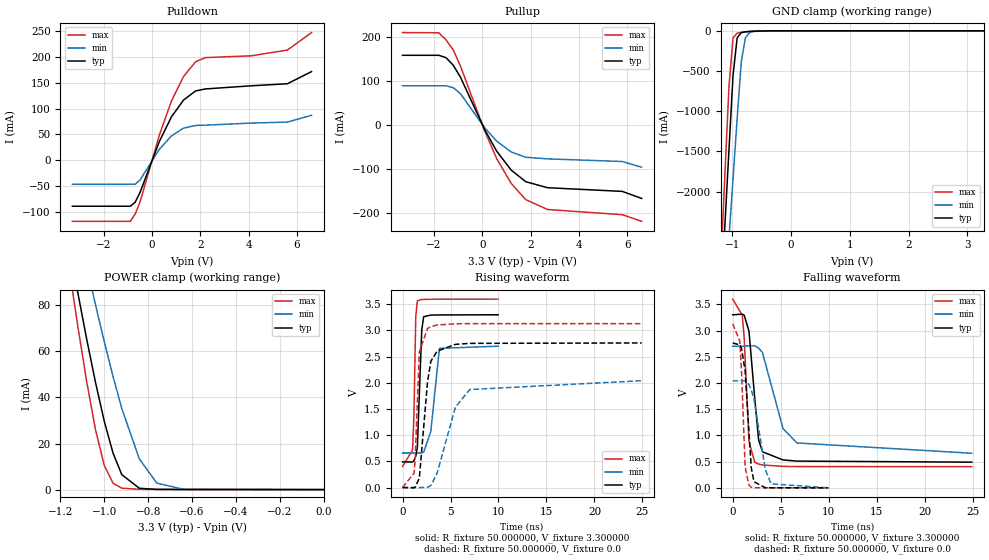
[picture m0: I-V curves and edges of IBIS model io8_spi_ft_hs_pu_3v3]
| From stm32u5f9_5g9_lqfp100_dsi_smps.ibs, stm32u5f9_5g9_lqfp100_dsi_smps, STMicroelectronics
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|   Model io8_spi_ft_hs_pu_3v3
[Model]  io8_spi_ft_hs_pu_3v3
Model_type I/O
Polarity   Non-Inverting
Enable   Active-Low
Vinl =   0.990000V
Vinh =   2.310000V
Vmeas =  1.650000V
Cref =   50.000000pF
Rref =   100.000000M
Vref =   0.0V
C_comp   3.495300pF   3.468500pF   3.534700pF
[Temperature Range]   25.000000   0.140000k   -40.000000
[Pullup Reference]   3.300000V   2.700000V   3.600000V
[Pulldown Reference]   0.0V   0.0V   0.0V
[POWER Clamp Reference]   3.300000V   2.700000V   3.600000V
[GND Clamp Reference]   0.0V   0.0V   0.0V
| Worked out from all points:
|   slope of the pulldown table from 0 to 0.495 V, typ, clamps not added: 8.73 ohm
|   slope of the pullup table from 0 to 0.495 V, typ, clamps not added: 9.64 ohm
|   GND clamp passes 1 mA (typ) near -0.50 V on its own axis
|   POWER clamp passes 1 mA (typ) near -0.85 V on its own axis
|   rising waveform, R_fixture 50.000000, V_fixture 3.300000: 20-80 % time 280ps typ, 497ps min, 208ps max; typ from 0.491 V to 3.3 V
|   rising waveform, R_fixture 50.000000, V_fixture 0.0: 20-80 % time 739ps typ, 2ns min, 394ps max; typ from 0.001 V to 2.76 V
|   falling waveform, R_fixture 50.000000, V_fixture 3.300000: 20-80 % time 735ps typ, 1.64ns min, 475ps max; typ from 3.3 V to 0.491 V
|   falling waveform, R_fixture 50.000000, V_fixture 0.0: 20-80 % time 556ps typ, 1.05ns min, 388ps max; typ from 2.76 V to 0.001 V
[Pulldown]
|Voltage   I(typ)   I(min)   I(max)
-3.3V     -89.71mA   -47.06mA   -119mA
-900mV    -89.71mA   -47.06mA   -119mA
-700mV    -81.75mA   -47.06mA   -104.8mA
-500mV    -62.92mA   -38.71mA   -81.44mA
300mV     36.2mA     21.01mA    48.7mA
800mV     84.06mA    46.96mA    114.8mA
1.3V      116.7mA    62.08mA    162.4mA
1.8V      134.4mA    67.38mA    191.2mA
2.2V      138.3mA    67.91mA    199.2mA
4.1V      144.4mA    71.94mA    202.7mA
5.6V      148.4mA    73.89mA    213.9mA
6.6V      172mA      87.1mA     247.9mA
[Pullup]
|Voltage   I(typ)   I(min)   I(max)
-3.3V     157.6mA    88.27mA    209.3mA
-1.8V     157.6mA    88.27mA    208.8mA
-1.5V     152.2mA    88.27mA    192.7mA
-1.2V     135mA      83.91mA    169.8mA
-900mV    107.7mA    70.19mA    132.8mA
100mV     -11.39mA   -7.258mA   -14.51mA
600mV     -60.65mA   -37.83mA   -77.68mA
1.2V      -103.6mA   -62.35mA   -134mA
1.8V      -129.9mA   -74.33mA   -170.6mA
2.7V      -143.6mA   -78mA      -193.2mA
5.8V      -152mA     -84mA      -205mA
6.6V      -168mA     -97mA      -220mA
[GND_clamp]
|Voltage   I(typ)   I(min)   I(max)
-3.3V     -9.098A    -9.372A    -9.671A
-1.2V     -3.386A    -4.091A    -2.933A
-1.13V    -2.437A    -3.34A     -1.815A
-1.06V    -1.49A     -2.588A    -705.6mA
-990mV    -555.7mA   -1.839A    -89.03mA
-920mV    -88.12mA   -1.093A    -28.78mA
-850mV    -22.35mA   -387.4mA   -19.84mA
-780mV    -12.12mA   -88mA      -13.87mA
-710mV    -7.709mA   -22.52mA   -8.846mA
-640mV    -4.545mA   -7.864mA   -4.87mA
-360mV    -31.12uA   -173.5uA   -8.496uA
3.28V     0A         14.15nA    -7.901nA
[POWER_clamp]
|Voltage   I(typ)   I(min)   I(max)
-3.28V    1.355A     1.167A     1.665A
-1.16V    105.8mA    131.6mA    95.87mA
-1.12V    85.08mA    114mA      70.45mA
-1.08V    65.17mA    96.88mA    46.73mA
-1.04V    46.48mA    80.2mA     25.96mA
-1V       29.63mA    64.18mA    10.49mA
-960mV    15.81mA    49.06mA    2.743mA
-920mV    6.481mA    35.16mA    612.1uA
-840mV    577.5uA    13.29mA    137.7uA
-760mV    93.74uA    2.807mA    97.79uA
-640mV    40.06uA    158.9uA    59.34uA
0V        0A         19.33nA    0A
[Ramp]
| variable   typ   min   max
dV/dt_r  1.65687/0.73677n   1.22436/1.99343n   1.87825/0.39110n
dV/dt_f  1.68569/0.73217n   1.22296/1.64230n   1.91752/0.47311n
R_load = 50.000000
[Rising Waveform]
R_fixture= 50.000000
V_fixture= 3.300000
V_fixture_min= 2.700000
V_fixture_max= 3.600000
|time   V(typ)   V(min)   V(max)
0s        490.5mV    660.4mV    404.2mV
1.041ns   488.5mV    660.4mV    716.5mV
1.181ns   509.2mV    660.4mV    1.33V
1.381ns   602.4mV    660.3mV    3.262V
1.542ns   762.6mV    660mV      3.567V
2.002ns   3.006V     660.8mV    3.592V
2.202ns   3.263V     677.6mV    3.593V
2.943ns   3.294V     1.066V     3.596V
3.844ns   3.297V     2.659V     3.598V
9.97ns    3.3V       2.7V       3.599V
[Rising Waveform]
R_fixture= 50.000000
V_fixture= 0.0
V_fixture_min= 0.0
V_fixture_max= 0.0
|time   V(typ)   V(min)   V(max)
0s        560.7uV    599.6uV    587uV
1.201ns   -5.574mV   645.2uV    278.2mV
1.301ns   5.559mV    670.9uV    492.1mV
1.752ns   179.1mV    -215.6uV   2.588V
2.603ns   2.017V     2.953mV    3.038V
2.953ns   2.413V     39.96mV    3.072V
3.604ns   2.604V     274.8mV    3.105V
5.506ns   2.735V     1.535V     3.128V
7.007ns   2.754V     1.872V     3.131V
24.92ns   2.762V     2.041V     3.131V
[Falling Waveform]
R_fixture= 50.000000
V_fixture= 3.300000
V_fixture_min= 2.700000
V_fixture_max= 3.600000
|time   V(typ)   V(min)   V(max)
0s        3.3V       2.7V       3.599V
1.001ns   3.312V     2.7V       3.295V
1.201ns   3.293V     2.701V     2.864V
1.702ns   2.987V     2.709V     882.2mV
2.302ns   1.708V     2.708V     488.3mV
2.703ns   918.8mV    2.665V     455mV
3.103ns   688.4mV    2.581V     437.2mV
5.255ns   533mV      1.128V     410.1mV
6.707ns   510.9mV    856.6mV    406.4mV
24.92ns   490.5mV    660.4mV    404.2mV
[Falling Waveform]
R_fixture= 50.000000
V_fixture= 0.0
V_fixture_min= 0.0
V_fixture_max= 0.0
|time   V(typ)   V(min)   V(max)
0s        2.762V     2.041V     3.131V
740.7ps   2.728V     2.041V     2.801V
920.9ps   2.66V      2.042V     2.237V
1.301ns   2.233V     2.041V     399.4mV
1.682ns   1.116V     1.974V     57mV
1.942ns   379.2mV    1.87V      9.857mV
2.222ns   117.2mV    1.694V     3.664mV
3.403ns   2.911mV    347.9mV    1.67mV
4.004ns   2.039mV    77.3mV     1.393mV
9.97ns    560.7uV    599.6uV    587uV
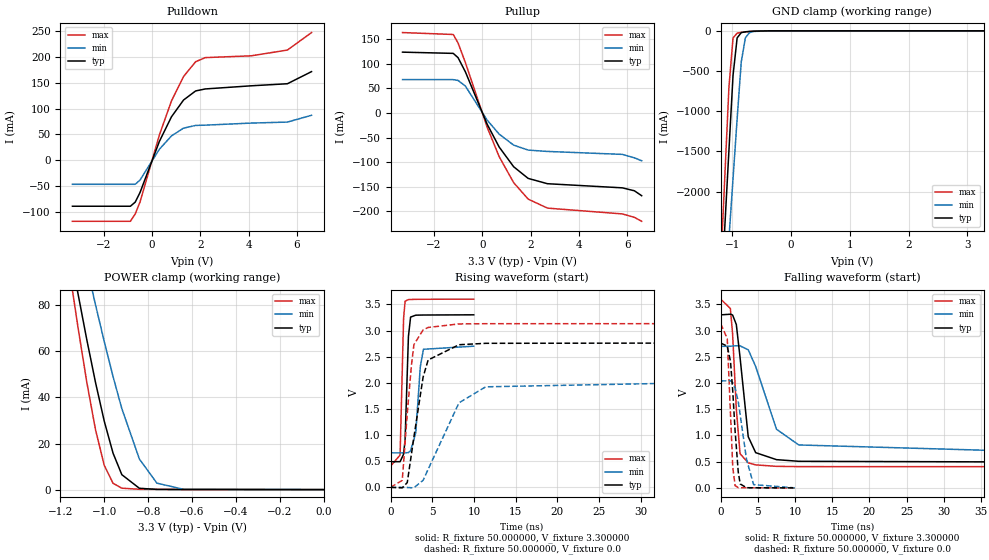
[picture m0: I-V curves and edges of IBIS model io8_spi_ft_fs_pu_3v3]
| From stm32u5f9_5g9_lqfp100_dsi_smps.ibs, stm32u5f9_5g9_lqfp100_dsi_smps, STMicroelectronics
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|   Model io8_spi_ft_fs_pu_3v3
[Model]  io8_spi_ft_fs_pu_3v3
Model_type I/O
Polarity   Non-Inverting
Enable   Active-Low
Vinl =   0.990000V
Vinh =   2.310000V
Vmeas =  1.650000V
Cref =   50.000000pF
Rref =   100.000000M
Vref =   0.0V
C_comp   3.495300pF   3.468500pF   3.534700pF
[Temperature Range]   25.000000   0.140000k   -40.000000
[Pullup Reference]   3.300000V   2.700000V   3.600000V
[Pulldown Reference]   0.0V   0.0V   0.0V
[POWER Clamp Reference]   3.300000V   2.700000V   3.600000V
[GND Clamp Reference]   0.0V   0.0V   0.0V
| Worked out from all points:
|   slope of the pulldown table from 0 to 0.495 V, typ, clamps not added: 8.73 ohm
|   slope of the pullup table from 0 to 0.495 V, typ, clamps not added: 9.64 ohm
|   GND clamp passes 1 mA (typ) near -0.50 V on its own axis
|   POWER clamp passes 1 mA (typ) near -0.85 V on its own axis
|   rising waveform, R_fixture 50.000000, V_fixture 3.300000: 20-80 % time 322ps typ, 517ps min, 255ps max; typ from 0.491 V to 3.3 V
|   rising waveform, R_fixture 50.000000, V_fixture 0.0: 20-80 % time 1.6ns typ, 3.59ns min, 972ps max; typ from 0.001 V to 2.76 V
|   falling waveform, R_fixture 50.000000, V_fixture 3.300000: 20-80 % time 1.16ns typ, 2.96ns min, 707ps max; typ from 3.3 V to 0.491 V
|   falling waveform, R_fixture 50.000000, V_fixture 0.0: 20-80 % time 758ps typ, 1.29ns min, 517ps max; typ from 2.76 V to 0.001 V
[Pulldown]
|Voltage   I(typ)   I(min)   I(max)
-3.3V     -89.71mA   -47.06mA   -119mA
-900mV    -89.71mA   -47.06mA   -119mA
-700mV    -81.75mA   -47.06mA   -104.8mA
-500mV    -62.92mA   -38.71mA   -81.44mA
300mV     36.2mA     21.01mA    48.7mA
800mV     84.06mA    46.96mA    114.8mA
1.3V      116.7mA    62.08mA    162.4mA
1.8V      134.4mA    67.38mA    191.2mA
2.2V      138.3mA    67.91mA    199.2mA
4.1V      144.4mA    71.94mA    202.7mA
5.6V      148.4mA    73.89mA    213.9mA
6.6V      172mA      87.1mA     247.9mA
[Pullup]
|Voltage   I(typ)   I(min)   I(max)
-3.3V     123.8mA    67.93mA    163.6mA
-1.2V     121.3mA    67.93mA    159.7mA
-1V       112.5mA    66.3mA     142.3mA
-700mV    83.97mA    54.95mA    102.9mA
200mV     -22.26mA   -14.13mA   -28.38mA
700mV     -69mA      -42.82mA   -88.5mA
1.3V      -109.1mA   -65.19mA   -141.4mA
1.9V      -132.8mA   -75.24mA   -174.9mA
2.7V      -143.6mA   -78mA      -193.2mA
5.8V      -152mA     -84mA      -205mA
6.3V      -158mA     -91mA      -212mA
6.6V      -168mA     -97mA      -220mA
[GND_clamp]
|Voltage   I(typ)   I(min)   I(max)
-3.3V     -9.098A    -9.372A    -9.671A
-1.2V     -3.386A    -4.091A    -2.933A
-1.13V    -2.437A    -3.34A     -1.815A
-1.06V    -1.49A     -2.588A    -705.6mA
-990mV    -555.7mA   -1.839A    -89.03mA
-920mV    -88.12mA   -1.093A    -28.78mA
-850mV    -22.35mA   -387.4mA   -19.84mA
-780mV    -12.12mA   -88mA      -13.87mA
-710mV    -7.709mA   -22.52mA   -8.846mA
-640mV    -4.545mA   -7.864mA   -4.87mA
-360mV    -31.12uA   -173.5uA   -8.496uA
3.28V     0A         14.15nA    -7.901nA
[POWER_clamp]
|Voltage   I(typ)   I(min)   I(max)
-3.28V    1.355A     1.167A     1.665A
-1.16V    105.8mA    131.6mA    95.87mA
-1.12V    85.08mA    114mA      70.45mA
-1.08V    65.17mA    96.88mA    46.73mA
-1.04V    46.48mA    80.2mA     25.96mA
-1V       29.63mA    64.18mA    10.49mA
-960mV    15.81mA    49.06mA    2.743mA
-920mV    6.481mA    35.16mA    612.1uA
-840mV    577.5uA    13.29mA    137.7uA
-760mV    93.74uA    2.807mA    97.79uA
-640mV    40.06uA    158.9uA    59.34uA
0V        0A         19.33nA    0A
[Ramp]
| variable   typ   min   max
dV/dt_r  1.65687/1.59893n   1.22436/3.58621n   1.87825/0.97152n
dV/dt_f  1.68569/1.16019n   1.22372/2.95606n   1.91752/0.70479n
R_load = 50.000000
[Rising Waveform]
R_fixture= 50.000000
V_fixture= 3.300000
V_fixture_min= 2.700000
V_fixture_max= 3.600000
|time   V(typ)   V(min)   V(max)
0s        490.5mV    660.4mV    404.1mV
1.141ns   491.8mV    660.4mV    618.1mV
1.562ns   634.7mV    660.1mV    3.233V
1.742ns   913mV      659.2mV    3.561V
2.142ns   2.889V     666.1mV    3.591V
2.402ns   3.257V     701.2mV    3.593V
3.023ns   3.293V     1.042V     3.596V
3.564ns   3.295V     2.305V     3.597V
3.944ns   3.296V     2.641V     3.597V
9.97ns    3.3V       2.7V       3.6V
[Rising Waveform]
R_fixture= 50.000000
V_fixture= 0.0
V_fixture_min= 0.0
V_fixture_max= 0.0
|time   V(typ)   V(min)   V(max)
0s        561.9uV    600uV      579.7uV
1.401ns   -9.132mV   675.6uV    134.3mV
2.002ns   92.46mV    -1.493mV   1.413V
2.503ns   638mV      -7.229mV   2.338V
2.803ns   966.3mV    -6.603mV   2.731V
3.904ns   2.111V     135.1mV    3.011V
4.505ns   2.436V     345.7mV    3.058V
8.208ns   2.728V     1.617V     3.126V
11.41ns   2.755V     1.923V     3.13V
49.85ns   2.762V     2.041V     3.131V
[Falling Waveform]
R_fixture= 50.000000
V_fixture= 3.300000
V_fixture_min= 2.700000
V_fixture_max= 3.600000
|time   V(typ)   V(min)   V(max)
0s        3.3V       2.7V       3.6V
1.301ns   3.312V     2.701V     3.422V
1.602ns   3.297V     2.706V     2.936V
2.102ns   3.116V     2.71V      1.505V
2.603ns   2.491V     2.708V     651.5mV
3.704ns   976.7mV    2.634V     477.6mV
4.705ns   671.9mV    2.316V     438.9mV
7.508ns   538.4mV    1.118V     410.9mV
10.51ns   507.1mV    818.7mV    405.8mV
49.85ns   490.5mV    660.4mV    404.1mV
[Falling Waveform]
R_fixture= 50.000000
V_fixture= 0.0
V_fixture_min= 0.0
V_fixture_max= 0.0
|time   V(typ)   V(min)   V(max)
0s        2.762V     2.041V     3.131V
880.9ps   2.703V     2.041V     2.848V
1.321ns   2.409V     2.044V     1.404V
1.622ns   1.845V     2.007V     391mV
1.942ns   1.077V     1.901V     42.18mV
2.362ns   302.3mV    1.642V     4.21mV
2.623ns   75.33mV    1.391V     3.133mV
3.463ns   3.628mV    551.2mV    1.908mV
4.424ns   2.004mV    62.32mV    1.403mV
9.97ns    561.9uV    600uV      579.7uV
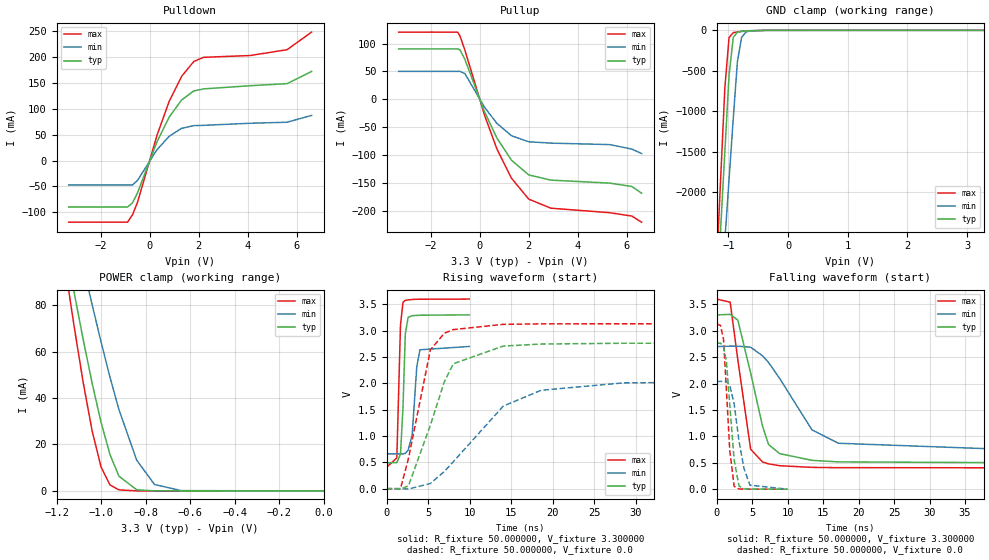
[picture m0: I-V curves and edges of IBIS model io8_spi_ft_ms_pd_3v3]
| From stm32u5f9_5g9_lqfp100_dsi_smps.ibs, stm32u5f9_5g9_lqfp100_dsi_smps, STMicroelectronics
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|   Model io8_spi_ft_ms_pd_3v3
[Model]  io8_spi_ft_ms_pd_3v3
Model_type I/O
Polarity   Non-Inverting
Enable   Active-Low
Vinl =   0.990000V
Vinh =   2.310000V
Vmeas =  1.650000V
Cref =   50.000000pF
Rref =   100.000000M
Vref =   0.0V
C_comp   3.495300pF   3.468500pF   3.534700pF
[Temperature Range]   25.000000   0.140000k   -40.000000
[Pullup Reference]   3.300000V   2.700000V   3.600000V
[Pulldown Reference]   0.0V   0.0V   0.0V
[POWER Clamp Reference]   3.300000V   2.700000V   3.600000V
[GND Clamp Reference]   0.0V   0.0V   0.0V
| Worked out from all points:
|   slope of the pulldown table from 0 to 0.495 V, typ, clamps not added: 8.73 ohm
|   slope of the pullup table from 0 to 0.495 V, typ, clamps not added: 9.64 ohm
|   GND clamp passes 1 mA (typ) near -0.50 V on its own axis
|   POWER clamp passes 1 mA (typ) near -0.85 V on its own axis
|   rising waveform, R_fixture 50.000000, V_fixture 3.300000: 20-80 % time 328ps typ, 511ps min, 284ps max; typ from 0.49 V to 3.3 V
|   rising waveform, R_fixture 50.000000, V_fixture 0.0: 20-80 % time 3.45ns typ, 7.17ns min, 2.35ns max; typ from 0 V to 2.76 V
|   falling waveform, R_fixture 50.000000, V_fixture 3.300000: 20-80 % time 2.77ns typ, 5.95ns min, 1.85ns max; typ from 3.3 V to 0.49 V
|   falling waveform, R_fixture 50.000000, V_fixture 0.0: 20-80 % time 942ps typ, 1.38ns min, 765ps max; typ from 2.76 V to 0 V
[Pulldown]
|Voltage   I(typ)   I(min)   I(max)
-3.3V     -89.72mA   -47.06mA   -119mA
-900mV    -89.72mA   -47.06mA   -119mA
-700mV    -81.75mA   -47.06mA   -104.8mA
-500mV    -62.92mA   -38.71mA   -81.44mA
300mV     36.2mA     21.01mA    48.7mA
800mV     84.06mA    46.96mA    114.8mA
1.3V      116.7mA    62.08mA    162.3mA
1.8V      134.4mA    67.38mA    191.2mA
2.2V      138.3mA    67.91mA    199.2mA
4.1V      144.4mA    71.97mA    202.7mA
5.6V      148.4mA    73.93mA    213.9mA
6.6V      171.9mA    87.1mA     247.9mA
[Pullup]
|Voltage   I(typ)   I(min)   I(max)
-3.3V     90.49mA    50.17mA    120.6mA
-900mV    90.49mA    50.17mA    120.6mA
-800mV    88.71mA    50.17mA    113.4mA
-600mV    71.5mA     46.18mA    88.11mA
200mV     -22.26mA   -14.13mA   -28.39mA
700mV     -69mA      -42.82mA   -88.5mA
1.3V      -109.1mA   -65.19mA   -141.4mA
2V        -135.3mA   -75.91mA   -178.7mA
2.9V      -144.6mA   -78.33mA   -194.9mA
5.3V      -150mA     -81mA      -203mA
6.2V      -156mA     -89mA      -209mA
6.6V      -168mA     -97mA      -220mA
[GND_clamp]
|Voltage   I(typ)   I(min)   I(max)
-3.3V     -9.098A    -9.372A    -9.671A
-1.2V     -3.386A    -4.091A    -2.933A
-1.13V    -2.437A    -3.34A     -1.815A
-1.06V    -1.49A     -2.588A    -705.6mA
-990mV    -555.7mA   -1.839A    -89.05mA
-920mV    -88.14mA   -1.093A    -28.79mA
-850mV    -22.36mA   -387.4mA   -19.86mA
-780mV    -12.13mA   -88.01mA   -13.89mA
-710mV    -7.72mA    -22.53mA   -8.86mA
-640mV    -4.556mA   -7.872mA   -4.884mA
-360mV    -39.69uA   -179.8uA   -19.45uA
3.28V     83.52uA    56.87uA    102.4uA
[POWER_clamp]
|Voltage   I(typ)   I(min)   I(max)
-3.28V    1.355A     1.167A     1.664A
-1.16V    105.7mA    131.6mA    95.69mA
-1.12V    84.97mA    114mA      70.27mA
-1.08V    65.05mA    96.83mA    46.54mA
-1.04V    46.34mA    80.15mA    25.76mA
-1V       29.51mA    64.13mA    10.3mA
-960mV    15.69mA    48.99mA    2.571mA
-920mV    6.373mA    35.1mA     455.6uA
-840mV    490.7uA    13.24mA    11.36uA
-760mV    27.33uA    2.767mA    279.3nA
-640mV    348nA      134.1uA    17.45nA
0V        0A         19.95nA    0A
[Ramp]
| variable   typ   min   max
dV/dt_r  1.65672/3.44785n   1.22412/7.15464n   1.87812/2.34329n
dV/dt_f  1.68574/2.76693n   1.22256/5.93314n   1.91751/1.84580n
R_load = 50.000000
[Rising Waveform]
R_fixture= 50.000000
V_fixture= 3.300000
V_fixture_min= 2.700000
V_fixture_max= 3.600000
|time   V(typ)   V(min)   V(max)
0s        489.8mV    659.6mV    403.4mV
1.241ns   493.7mV    659.6mV    582.7mV
1.682ns   654.8mV    659.1mV    3.105V
1.982ns   1.536V     658.2mV    3.539V
2.262ns   2.938V     669mV      3.575V
2.603ns   3.253V     729.9mV    3.583V
3.083ns   3.284V     1.011V     3.591V
3.644ns   3.289V     2.312V     3.595V
4.024ns   3.292V     2.636V     3.596V
9.97ns    3.299V     2.699V     3.599V
[Rising Waveform]
R_fixture= 50.000000
V_fixture= 0.0
V_fixture_min= 0.0
V_fixture_max= 0.0
|time   V(typ)   V(min)   V(max)
0s        5.335uV    5.69uV     3.577uV
1.682ns   -10.94mV   162.2uV    -3.32mV
2.643ns   51.76mV    -7.561mV   572.2mV
5.285ns   1.206V     96.34mV    2.635V
6.967ns   2.03V      325.5mV    2.951V
8.048ns   2.371V     510.6mV    3.019V
14.05ns   2.706V     1.565V     3.119V
18.62ns   2.745V     1.867V     3.128V
28.59ns   2.76V      2.008V     3.13V
59.82ns   2.761V     2.04V      3.13V
[Falling Waveform]
R_fixture= 50.000000
V_fixture= 3.300000
V_fixture_min= 2.700000
V_fixture_max= 3.600000
|time   V(typ)   V(min)   V(max)
0s        3.299V     2.699V     3.599V
1.922ns   3.309V     2.708V     3.541V
3.003ns   3.2V       2.707V     2.444V
4.805ns   2.199V     2.688V     755.8mV
6.486ns   1.189V     2.524V     514.2mV
7.327ns   845.4mV    2.399V     479.2mV
8.889ns   673.3mV    2.097V     443.9mV
13.45ns   545.6mV    1.121V     412.5mV
17.18ns   516.2mV    869mV      406.8mV
59.82ns   489.8mV    659.6mV    403.4mV
[Falling Waveform]
R_fixture= 50.000000
V_fixture= 0.0
V_fixture_min= 0.0
V_fixture_max= 0.0
|time   V(typ)   V(min)   V(max)
0s        2.761V     2.04V      3.13V
560.6ps   2.765V     2.04V      3.1V
981ps     2.696V     2.041V     2.841V
1.401ns   2.413V     2.044V     1.859V
1.862ns   1.599V     1.963V     737.1mV
2.482ns   554mV      1.616V     53.44mV
3.163ns   60.21mV    910.4mV    3.234mV
3.864ns   5.916mV    394.5mV    1.389mV
4.705ns   2.021mV    75.77mV    771uV
9.97ns    5.335uV    5.69uV     3.577uV
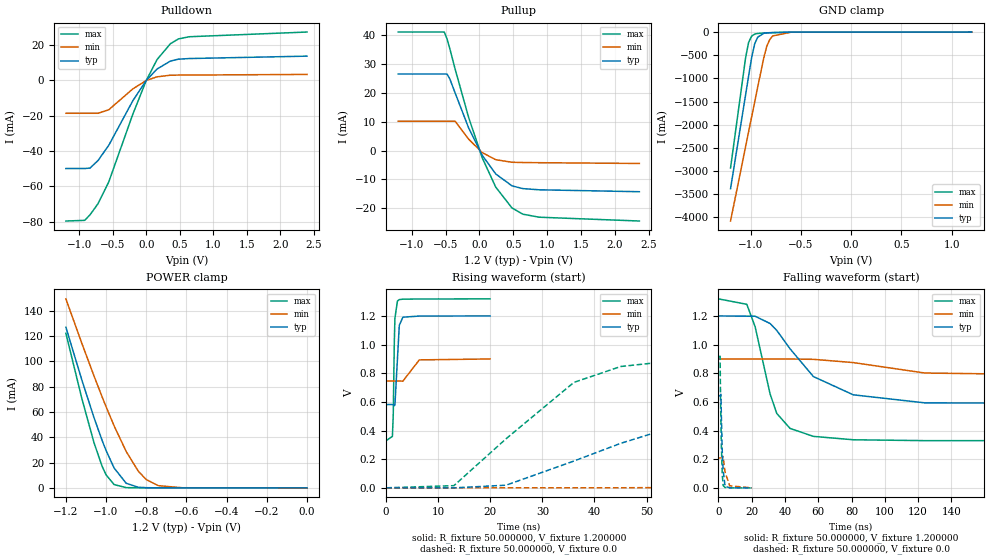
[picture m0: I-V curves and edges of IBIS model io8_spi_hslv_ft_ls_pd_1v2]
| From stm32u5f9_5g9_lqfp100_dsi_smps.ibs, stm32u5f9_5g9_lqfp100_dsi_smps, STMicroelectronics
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|   Model io8_spi_hslv_ft_ls_pd_1v2
[Model]  io8_spi_hslv_ft_ls_pd_1v2
Model_type I/O
Polarity   Non-Inverting
Enable   Active-Low
Vinl =   0.360000V
Vinh =   0.840000V
Vmeas =  0.600000V
Cref =   50.000000pF
Rref =   100.000000M
Vref =   0.0V
C_comp   3.133100pF   3.070300pF   3.178200pF
[Temperature Range]   25.000000   0.140000k   -40.000000
[Pullup Reference]   1.200000V   0.900000V   1.320000V
[Pulldown Reference]   0.0V   0.0V   0.0V
[POWER Clamp Reference]   1.200000V   0.900000V   1.320000V
[GND Clamp Reference]   0.0V   0.0V   0.0V
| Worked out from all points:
|   slope of the pulldown table from 0 to 0.18 V, typ, clamps not added: 25.4 ohm
|   slope of the pullup table from 0 to 0.18 V, typ, clamps not added: 27.8 ohm
|   GND clamp passes 1 mA (typ) near -0.51 V on its own axis
|   POWER clamp passes 1 mA (typ) near -0.86 V on its own axis
|   rising waveform, R_fixture 50.000000, V_fixture 1.200000: 20-80 % time 432ps typ, 1.04ns min, 256ps max; typ from 0.581 V to 1.2 V
|   rising waveform, R_fixture 50.000000, V_fixture 0.0: 20-80 % time 33.7ns typ, 83ns min, 17.1ns max; typ from 0 V to 0.642 V
|   falling waveform, R_fixture 50.000000, V_fixture 1.200000: 20-80 % time 30.3ns typ, 71ns min, 12.6ns max; typ from 1.2 V to 0.581 V
|   falling waveform, R_fixture 50.000000, V_fixture 0.0: 20-80 % time 1.06ns typ, 1.81ns min, 831ps max; typ from 0.642 V to 0 V
[Pulldown]
|Voltage   I(typ)   I(min)   I(max)
-1.2V     -49.85mA   -18.56mA   -79.56mA
-920mV    -49.85mA   -18.56mA   -79.19mA
-840mV    -49.59mA   -18.56mA   -76.08mA
-720mV    -45.32mA   -18.56mA   -69.74mA
-560mV    -36.71mA   -16.58mA   -57.44mA
-200mV    -11.43mA   -4.738mA   -19.03mA
0V        -10fA      -1.1pA     0A
160mV     6.476mA    2.074mA    11.78mA
360mV     10.99mA    2.987mA    20.81mA
480mV     12.07mA    3.051mA    23.52mA
640mV     12.42mA    3.072mA    24.76mA
2.4V      13.78mA    3.431mA    27.43mA
[Pullup]
|Voltage   I(typ)   I(min)   I(max)
-1.2V     26.53mA    10.15mA    41.1mA
-520mV    26.53mA    10.15mA    41.1mA
-480mV    26.53mA    10.15mA    38.78mA
-440mV    24.95mA    10.15mA    35.49mA
-360mV    19.99mA    10.15mA    28.26mA
-160mV    7.809mA    3.929mA    11.44mA
40mV      -1.648mA   -721.1uA   -2.521mA
240mV     -8.14mA    -3.199mA   -12.72mA
480mV     -12.27mA   -4.076mA   -19.94mA
640mV     -13.22mA   -4.167mA   -22.09mA
880mV     -13.63mA   -4.229mA   -23.14mA
2.36V     -14.3mA    -4.5mA     -24.46mA
[GND_clamp]
|Voltage   I(typ)   I(min)   I(max)
-1.2V     -3.379A    -4.076A    -2.932A
-1.05V    -1.35A     -2.47A     -550.7mA
-1.02V    -947.8mA   -2.15A     -221.5mA
-990mV    -552.4mA   -1.829A    -88.45mA
-960mV    -255.3mA   -1.51A     -44.89mA
-930mV    -111.8mA   -1.191A    -30.69mA
-870mV    -28.36mA   -564.6mA   -21.36mA
-840mV    -18.66mA   -309.5mA   -18.51mA
-810mV    -14.08mA   -161.6mA   -15.94mA
-780mV    -11.38mA   -83.33mA   -13.55mA
-600mV    -3.019mA   -4.329mA   -3.104mA
1.2V      30.28uA    18.17uA    37.27uA
[POWER_clamp]
|Voltage   I(typ)   I(min)   I(max)
-1.2V     127mA      149.4mA    122.2mA
-1.12V    84.97mA    114mA      70.27mA
-1.06V    55.51mA    88.42mA    35.67mA
-1.02V    37.63mA    72.04mA    17.17mA
-1V       29.51mA    64.13mA    10.3mA
-960mV    15.69mA    48.99mA    2.571mA
-900mV    3.624mA    28.77mA    182.8uA
-840mV    490.7uA    13.24mA    11.35uA
-800mV    116.8uA    6.532mA    1.77uA
-740mV    13.2uA     1.723mA    109.1nA
-620mV    167.4nA    79.36uA    0A
0V        0A         17.87nA    0A
[Ramp]
| variable   typ   min   max
dV/dt_r  0.38524/33.61392n   0.12527/82.97350n   0.54788/17.05978n
dV/dt_f  0.37090/30.29645n   92.58600m/70.97582n 0.59417/12.60837n
R_load = 50.000000
[Rising Waveform]
R_fixture= 50.000000
V_fixture= 1.200000
V_fixture_min= 0.900000
V_fixture_max= 1.320000
|time   V(typ)   V(min)   V(max)
0s        581.3mV    745.3mV    329.2mV
1.201ns   581.3mV    745.3mV    358.9mV
1.361ns   579.2mV    745.3mV    508.2mV
1.562ns   573.1mV    745.3mV    1.011V
1.682ns   578.5mV    745.3mV    1.183V
2.162ns   895.9mV    745.3mV    1.304V
2.523ns   1.134V     745.3mV    1.314V
3.203ns   1.191V     744.6mV    1.317V
6.366ns   1.199V     893mV      1.318V
19.94ns   1.2V       899.5mV    1.319V
[Rising Waveform]
R_fixture= 50.000000
V_fixture= 0.0
V_fixture_min= 0.0
V_fixture_max= 0.0
|time   V(typ)   V(min)   V(max)
0s        1.941nV    235.3nV    1.147nV
13.01ns   -194.1uV   -104.9uV   15.11mV
23.02ns   18.33mV    -69.91uV   342.5mV
36.04ns   186.8mV    140.4uV    735.9mV
45.05ns   310.9mV    353.7uV    847mV
57.06ns   446.2mV    2.529mV    893.3mV
79.08ns   578.9mV    24.65mV    910.4mV
112.1ns   631.7mV    85.85mV    913.1mV
209.2ns   642mV      190.8mV    913.1mV
498.5ns   642.1mV    208.9mV    913.1mV
[Falling Waveform]
R_fixture= 50.000000
V_fixture= 1.200000
V_fixture_min= 0.900000
V_fixture_max= 1.320000
|time   V(typ)   V(min)   V(max)
0s        1.2V       899.5mV    1.319V
17.02ns   1.198V     899.3mV    1.281V
22.02ns   1.198V     899.1mV    1.125V
31.03ns   1.147V     899.1mV    655.6mV
35.04ns   1.099V     899.1mV    519.4mV
43.04ns   970.4mV    899mV      414.8mV
57.06ns   776.8mV    897mV      359.3mV
81.08ns   649.2mV    874.3mV    335.5mV
124.1ns   593.2mV    801.4mV    329.5mV
498.5ns   581.3mV    745.3mV    329.2mV
[Falling Waveform]
R_fixture= 50.000000
V_fixture= 0.0
V_fixture_min= 0.0
V_fixture_max= 0.0
|time   V(typ)   V(min)   V(max)
0s        642.1mV    208.9mV    913.1mV
961ps     642.2mV    209mV      918.9mV
1.321ns   652.6mV    209.1mV    549.4mV
1.481ns   653.1mV    209.1mV    451.7mV
1.762ns   484.1mV    209.1mV    282.6mV
2.282ns   246.8mV    208.9mV    91.8mV
2.803ns   124.2mV    217.1mV    16.74mV
3.924ns   11.82mV    110.9mV    1.988mV
6.727ns   364.6uV    14.35mV    28.95uV
19.94ns   1.941nV    235.3nV    1.147nV
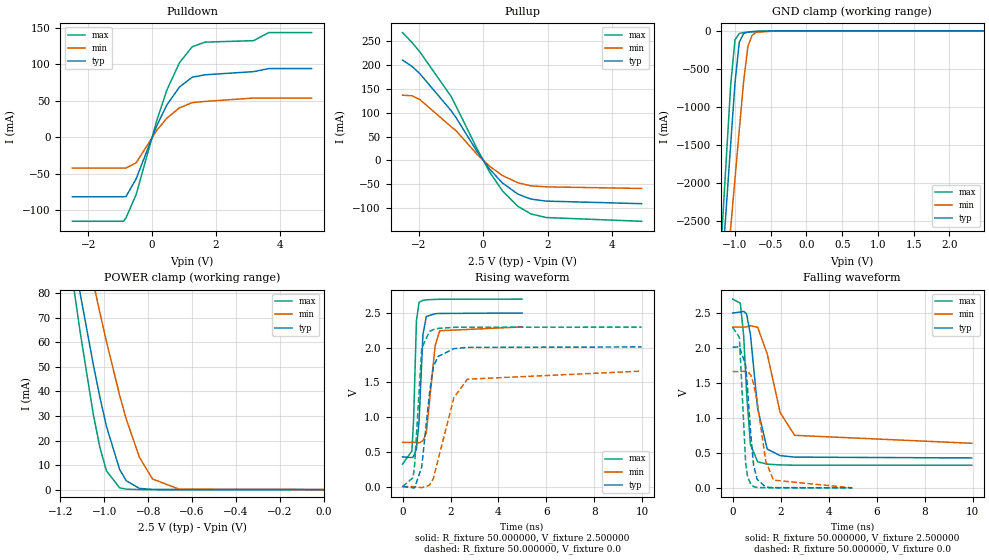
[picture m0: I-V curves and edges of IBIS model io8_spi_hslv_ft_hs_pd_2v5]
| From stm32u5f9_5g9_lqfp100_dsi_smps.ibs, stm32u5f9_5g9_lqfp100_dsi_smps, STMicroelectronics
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|   Model io8_spi_hslv_ft_hs_pd_2v5
[Model]  io8_spi_hslv_ft_hs_pd_2v5
Model_type I/O
Polarity   Non-Inverting
Enable   Active-Low
Vinl =   0.750000V
Vinh =   1.750000V
Vmeas =  1.250000V
Cref =   50.000000pF
Rref =   100.000000M
Vref =   0.0V
C_comp   3.438200pF   3.436700pF   3.473300pF
[Temperature Range]   25.000000   0.140000k   -40.000000
[Pullup Reference]   2.500000V   2.300000V   2.700000V
[Pulldown Reference]   0.0V   0.0V   0.0V
[POWER Clamp Reference]   2.500000V   2.300000V   2.700000V
[GND Clamp Reference]   0.0V   0.0V   0.0V
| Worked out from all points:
|   slope of the pulldown table from 0 to 0.375 V, typ, clamps not added: 10.1 ohm
|   slope of the pullup table from 0 to 0.375 V, typ, clamps not added: 11.7 ohm
|   GND clamp passes 1 mA (typ) near -0.50 V on its own axis
|   POWER clamp passes 1 mA (typ) near -0.86 V on its own axis
|   rising waveform, R_fixture 50.000000, V_fixture 2.500000: 20-80 % time 161ps typ, 245ps min, 120ps max; typ from 0.428 V to 2.5 V
|   rising waveform, R_fixture 50.000000, V_fixture 0.0: 20-80 % time 384ps typ, 750ps min, 231ps max; typ from 0 V to 2.01 V
|   falling waveform, R_fixture 50.000000, V_fixture 2.500000: 20-80 % time 371ps typ, 700ps min, 233ps max; typ from 2.5 V to 0.428 V
|   falling waveform, R_fixture 50.000000, V_fixture 0.0: 20-80 % time 262ps typ, 442ps min, 182ps max; typ from 2.01 V to 0 V
[Pulldown]
|Voltage   I(typ)   I(min)   I(max)
-2.5V     -81.62mA   -42.31mA   -115.3mA
-900mV    -81.62mA   -42.31mA   -115.3mA
-820mV    -81.42mA   -42.31mA   -110.6mA
-500mV    -56.95mA   -35.08mA   -78.57mA
140mV     15.18mA    9.02mA     22.02mA
460mV     44mA       25.98mA    64.37mA
860mV     68.91mA    40.27mA    102.2mA
1.26V     82.21mA    47.42mA    124mA
1.66V     85.53mA    48.99mA    130.3mA
3.18V     89.84mA    53.65mA    132.3mA
3.66V     94.05mA    53.65mA    143.4mA
5V        94.05mA    53.65mA    143.4mA
[Pullup]
|Voltage   I(typ)   I(min)   I(max)
-2.5V     210.8mA    137mA      268.6mA
-2.2V     197.1mA    135.8mA    247.3mA
-1.96V    182mA      127.7mA    227.8mA
-1V       105.1mA    71.24mA    135.1mA
-840mV    90mA       62.56mA    114.1mA
-200mV    19.92mA    13.68mA    26.11mA
200mV     -18.15mA   -12.19mA   -24.3mA
600mV     -47.45mA   -31.77mA   -63.92mA
1.08V     -70.88mA   -47.09mA   -96.6mA
1.48V     -81.29mA   -53.4mA    -112.4mA
1.96V     -85.56mA   -55.61mA   -120.1mA
4.92V     -91mA      -59mA      -128mA
[GND_clamp]
|Voltage   I(typ)   I(min)   I(max)
-2.5V     -9.641A    -9.693A    -9.352A
-1.18V    -3.114A    -3.874A    -2.614A
-1.12V    -2.301A    -3.23A     -1.656A
-1.06V    -1.489A    -2.587A    -706.2mA
-1V       -685.8mA   -1.945A    -119.3mA
-940mV    -149.8mA   -1.304A    -34.74mA
-880mV    -35.55mA   -672.6mA   -23.08mA
-820mV    -16.2mA    -206.4mA   -17.29mA
-760mV    -10.59mA   -57.56mA   -12.42mA
-700mV    -7.162mA   -18.75mA   -8.254mA
-400mV    -112.4uA   -385.2uA   -53.46uA
2.48V     63.1uA     48.03uA    77.39uA
[POWER_clamp]
|Voltage   I(typ)   I(min)   I(max)
-2.49V    881mA      773.1mA    1.07A
-1.14V    95.25mA    122.7mA    82.82mA
-1.11V    79.9mA     109.7mA    64.14mA
-1.05V    50.87mA    84.26mA    30.57mA
-1.02V    37.63mA    72.04mA    17.17mA
-990mV    25.71mA    60.25mA    7.621mA
-930mV    8.217mA    38.43mA    713.9uA
-900mV    3.624mA    28.77mA    182.8uA
-840mV    490.7uA    13.24mA    11.35uA
-780mV    56.55uA    4.324mA    699nA
-660mV    716.7nA    226uA      9.786nA
0V        0A         19.53nA    0A
[Ramp]
| variable   typ   min   max
dV/dt_r  1.20630/0.38337n   0.99744/0.74886n   1.37748/0.23090n
dV/dt_f  1.24320/0.37029n   0.99718/0.69893n   1.42604/0.23201n
R_load = 50.000000
[Rising Waveform]
R_fixture= 50.000000
V_fixture= 2.500000
V_fixture_min= 2.300000
V_fixture_max= 2.700000
|time   V(typ)   V(min)   V(max)
0s        427.5mV    637.3mV    322.7mV
390.4ps   418mV      637.5mV    512.1mV
460.5ps   432.1mV    637.4mV    955.1mV
580.6ps   546.5mV    634.5mV    2.389V
690.7ps   948.1mV    629.6mV    2.654V
850.9ps   2.187V     659.5mV    2.682V
991ps     2.449V     772.9mV    2.689V
1.361ns   2.489V     2.032V     2.695V
1.552ns   2.493V     2.244V     2.697V
4.985ns   2.499V     2.299V     2.699V
[Rising Waveform]
R_fixture= 50.000000
V_fixture= 0.0
V_fixture_min= 0.0
V_fixture_max= 0.0
|time   V(typ)   V(min)   V(max)
0s        -18.19uV   -11.94uV   20.4uV
440.4ps   -17.25mV   134.2uV    128.5mV
500.5ps   -18.12mV   65.37uV    297.6mV
800.8ps   282.4mV    -15.84mV   1.99V
1.121ns   1.336V     21.17mV    2.233V
1.281ns   1.723V     112.7mV    2.26V
1.481ns   1.873V     385.1mV    2.278V
2.142ns   1.986V     1.28V      2.293V
2.703ns   2.004V     1.546V     2.295V
9.97ns    2.011V     1.663V     2.296V
[Falling Waveform]
R_fixture= 50.000000
V_fixture= 2.500000
V_fixture_min= 2.300000
V_fixture_max= 2.700000
|time   V(typ)   V(min)   V(max)
0s        2.499V     2.299V     2.699V
320.3ps   2.515V     2.3V       2.641V
460.5ps   2.524V     2.299V     2.17V
580.6ps   2.486V     2.302V     1.358V
740.7ps   2.193V     2.319V     622.3mV
1.041ns   1.136V     2.297V     372.9mV
1.441ns   554.1mV    1.916V     339mV
1.982ns   460.7mV    1.075V     327.7mV
2.583ns   439.8mV    751.3mV    324.2mV
9.97ns    427.5mV    637.3mV    322.7mV
[Falling Waveform]
R_fixture= 50.000000
V_fixture= 0.0
V_fixture_min= 0.0
V_fixture_max= 0.0
|time   V(typ)   V(min)   V(max)
0s        2.011V     1.663V     2.296V
280.3ps   2.017V     1.663V     2.153V
540.5ps   1.758V     1.666V     363.1mV
620.6ps   1.421V     1.667V     158.9mV
760.8ps   747.7mV    1.609V     50.97mV
870.9ps   325.9mV    1.493V     17.77mV
1.021ns   120.5mV    1.231V     5.447mV
1.381ns   10.17mV    381.7mV    2.28mV
1.702ns   3.679mV    110.3mV    1.148mV
4.985ns   -18.19uV   -11.94uV   20.4uV
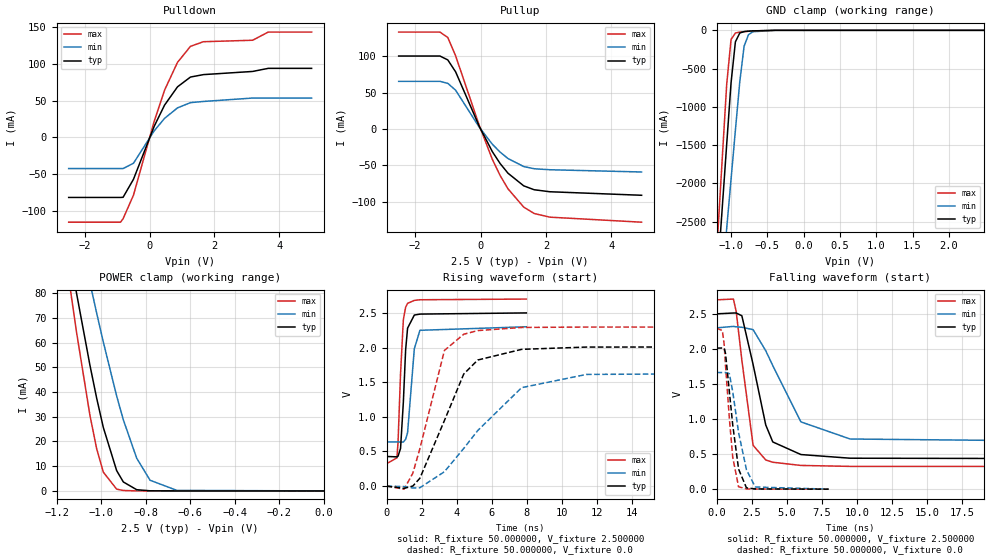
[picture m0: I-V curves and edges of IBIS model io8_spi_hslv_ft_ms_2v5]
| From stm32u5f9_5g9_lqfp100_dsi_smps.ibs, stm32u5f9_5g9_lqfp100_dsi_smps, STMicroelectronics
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|   Model io8_spi_hslv_ft_ms_2v5
[Model]  io8_spi_hslv_ft_ms_2v5
Model_type I/O
Polarity   Non-Inverting
Enable   Active-Low
Vinl =   0.750000V
Vinh =   1.750000V
Vmeas =  1.250000V
Cref =   50.000000pF
Rref =   100.000000M
Vref =   0.0V
C_comp   3.438200pF   3.436700pF   3.473300pF
[Temperature Range]   25.000000   0.140000k   -40.000000
[Pullup Reference]   2.500000V   2.300000V   2.700000V
[Pulldown Reference]   0.0V   0.0V   0.0V
[POWER Clamp Reference]   2.500000V   2.300000V   2.700000V
[GND Clamp Reference]   0.0V   0.0V   0.0V
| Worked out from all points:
|   slope of the pulldown table from 0 to 0.375 V, typ, clamps not added: 10.1 ohm
|   slope of the pullup table from 0 to 0.375 V, typ, clamps not added: 11.7 ohm
|   GND clamp passes 1 mA (typ) near -0.50 V on its own axis
|   POWER clamp passes 1 mA (typ) near -0.86 V on its own axis
|   rising waveform, R_fixture 50.000000, V_fixture 2.500000: 20-80 % time 226ps typ, 273ps min, 223ps max; typ from 0.428 V to 2.5 V
|   rising waveform, R_fixture 50.000000, V_fixture 0.0: 20-80 % time 1.91ns typ, 3.39ns min, 1.31ns max; typ from 0 V to 2.01 V
|   falling waveform, R_fixture 50.000000, V_fixture 2.500000: 20-80 % time 1.3ns typ, 2.44ns min, 854ps max; typ from 2.5 V to 0.428 V
|   falling waveform, R_fixture 50.000000, V_fixture 0.0: 20-80 % time 653ps typ, 857ps min, 533ps max; typ from 2.01 V to 0 V
[Pulldown]
|Voltage   I(typ)   I(min)   I(max)
-2.5V     -81.62mA   -42.31mA   -115.3mA
-900mV    -81.62mA   -42.31mA   -115.3mA
-820mV    -81.42mA   -42.31mA   -110.6mA
-500mV    -56.95mA   -35.08mA   -78.57mA
140mV     15.18mA    9.02mA     22.02mA
460mV     44mA       25.98mA    64.38mA
860mV     68.91mA    40.27mA    102.2mA
1.26V     82.21mA    47.42mA    124mA
1.66V     85.53mA    48.99mA    130.3mA
3.18V     89.84mA    53.65mA    132.3mA
3.66V     94.05mA    53.65mA    143.4mA
5V        94.05mA    53.65mA    143.4mA
[Pullup]
|Voltage   I(typ)   I(min)   I(max)
-2.5V     100.4mA    65.59mA    133.3mA
-1.24V    100.4mA    65.59mA    133.3mA
-1V       95.07mA    62.85mA    125.9mA
-760mV    78.59mA    53.37mA    100.6mA
-40mV     3.893mA    2.628mA    5.181mA
360mV     -30.97mA   -20.78mA   -41.56mA
600mV     -47.45mA   -31.77mA   -63.92mA
840mV     -60.71mA   -40.52mA   -82.21mA
1.32V     -78.06mA   -51.54mA   -107.3mA
1.64V     -83.42mA   -54.54mA   -116.1mA
2.12V     -86.16mA   -55.91mA   -121.1mA
4.92V     -91mA      -59mA      -128mA
[GND_clamp]
|Voltage   I(typ)   I(min)   I(max)
-2.5V     -9.641A    -9.693A    -9.352A
-1.18V    -3.114A    -3.874A    -2.614A
-1.12V    -2.301A    -3.23A     -1.656A
-1.06V    -1.489A    -2.587A    -706.2mA
-1V       -685.8mA   -1.945A    -119.3mA
-940mV    -149.7mA   -1.304A    -34.73mA
-880mV    -35.54mA   -672.6mA   -23.06mA
-820mV    -16.19mA   -206.4mA   -17.27mA
-760mV    -10.58mA   -57.55mA   -12.41mA
-700mV    -7.152mA   -18.74mA   -8.24mA
-400mV    -103.3uA   -378.5uA   -41.74uA
2.48V     0A         13.22nA    0A
[POWER_clamp]
|Voltage   I(typ)   I(min)   I(max)
-2.49V    881mA      773.1mA    1.07A
-1.14V    95.25mA    122.7mA    82.82mA
-1.11V    79.9mA     109.7mA    64.14mA
-1.05V    50.87mA    84.26mA    30.57mA
-1.02V    37.63mA    72.04mA    17.17mA
-990mV    25.71mA    60.25mA    7.621mA
-930mV    8.217mA    38.43mA    713.9uA
-900mV    3.624mA    28.77mA    182.8uA
-840mV    490.7uA    13.24mA    11.35uA
-780mV    56.55uA    4.324mA    699nA
-660mV    716.7nA    226uA      9.786nA
0V        0A         19.53nA    0A
[Ramp]
| variable   typ   min   max
dV/dt_r  1.20666/1.90566n   0.99780/3.38939n   1.37784/1.30616n
dV/dt_f  1.24344/1.30304n   0.99746/2.42982n   1.42636/0.85072n
R_load = 50.000000
[Rising Waveform]
R_fixture= 50.000000
V_fixture= 2.500000
V_fixture_min= 2.300000
V_fixture_max= 2.700000
|time   V(typ)   V(min)   V(max)
0s        427.6mV    637.6mV    322.7mV
592.6ps   421.8mV    637.6mV    407.5mV
656.7ps   431.3mV    637.5mV    630.6mV
800.8ps   543.9mV    634.9mV    1.626V
961ps     1.216V     636.4mV    2.405V
1.089ns   1.962V     675.3mV    2.581V
1.201ns   2.28V      769.9mV    2.638V
1.586ns   2.469V     1.982V     2.681V
1.906ns   2.483V     2.249V     2.69V
7.976ns   2.5V       2.3V       2.7V
[Rising Waveform]
R_fixture= 50.000000
V_fixture= 0.0
V_fixture_min= 0.0
V_fixture_max= 0.0
|time   V(typ)   V(min)   V(max)
0s        -1.565uV   -3.852uV   -7.384uV
1.001ns   -33.33mV   -6.99mV    -44.57mV
1.502ns   570.9uV    -27.17mV   185.8mV
1.902ns   112.8mV    -23.71mV   539.1mV
3.303ns   946mV      207.2mV    1.958V
4.404ns   1.617V     543.1mV    2.192V
5.205ns   1.82V      801.8mV    2.245V
7.708ns   1.974V     1.421V     2.29V
11.41ns   2.007V     1.612V     2.296V
49.85ns   2.011V     1.663V     2.296V
[Falling Waveform]
R_fixture= 50.000000
V_fixture= 2.500000
V_fixture_min= 2.300000
V_fixture_max= 2.700000
|time   V(typ)   V(min)   V(max)
0s        2.5V       2.3V       2.7V
1.201ns   2.512V     2.321V     2.711V
1.401ns   2.512V     2.315V     2.533V
1.802ns   2.473V     2.309V     1.841V
2.603ns   1.778V     2.275V     625.6mV
3.504ns   914.9mV    1.974V     415.8mV
4.004ns   673.4mV    1.762V     383.8mV
6.006ns   493.6mV    959.4mV    338.4mV
9.51ns    441.4mV    715.3mV    324.9mV
49.85ns   427.6mV    637.6mV    322.7mV
[Falling Waveform]
R_fixture= 50.000000
V_fixture= 0.0
V_fixture_min= 0.0
V_fixture_max= 0.0
|time   V(typ)   V(min)   V(max)
0s        2.011V     1.663V     2.296V
416.4ps   2.013V     1.663V     2.261V
544.5ps   2.01V      1.663V     2.065V
640.6ps   1.935V     1.663V     1.759V
912.9ps   1.392V     1.647V     1.011V
1.153ns   916.6mV    1.392V     455.4mV
1.57ns    285.6mV    806.7mV    33.83mV
2.13ns    19mV       278.1mV    3.289mV
2.755ns   3.584mV    30.94mV    1.777mV
7.976ns   -1.565uV   -3.852uV   -7.384uV
